VERSION 5.7 ;
  NOWIREEXTENSIONATPIN ON ;
  DIVIDERCHAR "/" ;
  BUSBITCHARS "[]" ;
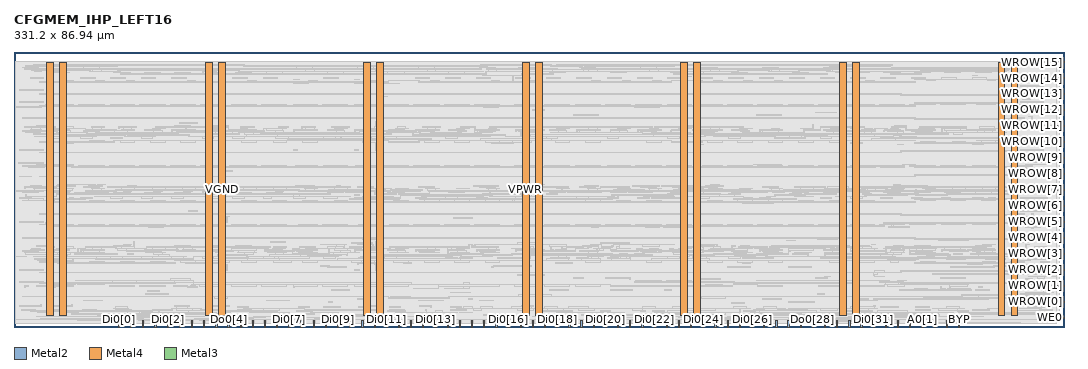
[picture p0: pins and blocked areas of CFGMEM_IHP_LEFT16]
MACRO CFGMEM_IHP_LEFT16
  CLASS BLOCK ;
  FOREIGN CFGMEM_IHP_LEFT16 ;
  ORIGIN 0.000 0.000 ;
  SIZE 331.200 BY 86.940 ;
  PIN A0[0]
    DIRECTION INPUT ;
    USE SIGNAL ;
    ANTENNAGATEAREA 0.213200 ;
    ANTENNADIFFAREA 2.015400 ;
    PORT
      LAYER Metal2 ;
        RECT 282.520 0.000 282.920 2.000 ;
    END
  END A0[0]
  PIN A0[1]
    DIRECTION INPUT ;
    USE SIGNAL ;
    ANTENNAGATEAREA 0.213200 ;
    ANTENNADIFFAREA 2.015400 ;
    PORT
      LAYER Metal2 ;
        RECT 286.360 0.000 286.760 2.000 ;
    END
  END A0[1]
  PIN A0[2]
    DIRECTION INPUT ;
    USE SIGNAL ;
    ANTENNAGATEAREA 0.213200 ;
    ANTENNADIFFAREA 2.015400 ;
    PORT
      LAYER Metal2 ;
        RECT 290.200 0.000 290.600 2.000 ;
    END
  END A0[2]
  PIN A0[3]
    DIRECTION INPUT ;
    USE SIGNAL ;
    ANTENNAGATEAREA 0.213200 ;
    ANTENNADIFFAREA 2.015400 ;
    PORT
      LAYER Metal2 ;
        RECT 294.040 0.000 294.440 2.000 ;
    END
  END A0[3]
  PIN BYP
    DIRECTION INPUT ;
    USE SIGNAL ;
    ANTENNAGATEAREA 0.213200 ;
    ANTENNADIFFAREA 2.015400 ;
    PORT
      LAYER Metal2 ;
        RECT 297.880 0.000 298.280 2.000 ;
    END
  END BYP
  PIN Di0[0]
    DIRECTION INPUT ;
    USE SIGNAL ;
    ANTENNAGATEAREA 0.406900 ;
    ANTENNADIFFAREA 4.030800 ;
    PORT
      LAYER Metal2 ;
        RECT 32.920 0.000 33.320 2.000 ;
    END
  END Di0[0]
  PIN Di0[10]
    DIRECTION INPUT ;
    USE SIGNAL ;
    ANTENNAGATEAREA 0.406900 ;
    ANTENNADIFFAREA 4.030800 ;
    PORT
      LAYER Metal2 ;
        RECT 109.720 0.000 110.120 2.000 ;
    END
  END Di0[10]
  PIN Di0[11]
    DIRECTION INPUT ;
    USE SIGNAL ;
    ANTENNAGATEAREA 0.406900 ;
    ANTENNADIFFAREA 4.030800 ;
    PORT
      LAYER Metal2 ;
        RECT 117.400 0.000 117.800 2.000 ;
    END
  END Di0[11]
  PIN Di0[12]
    DIRECTION INPUT ;
    USE SIGNAL ;
    ANTENNAGATEAREA 0.406900 ;
    ANTENNADIFFAREA 4.030800 ;
    PORT
      LAYER Metal2 ;
        RECT 125.080 0.000 125.480 2.000 ;
    END
  END Di0[12]
  PIN Di0[13]
    DIRECTION INPUT ;
    USE SIGNAL ;
    ANTENNAGATEAREA 0.406900 ;
    ANTENNADIFFAREA 4.030800 ;
    PORT
      LAYER Metal2 ;
        RECT 132.760 0.000 133.160 2.000 ;
    END
  END Di0[13]
  PIN Di0[14]
    DIRECTION INPUT ;
    USE SIGNAL ;
    ANTENNAGATEAREA 0.406900 ;
    ANTENNADIFFAREA 4.030800 ;
    PORT
      LAYER Metal2 ;
        RECT 140.440 0.000 140.840 2.000 ;
    END
  END Di0[14]
  PIN Di0[15]
    DIRECTION INPUT ;
    USE SIGNAL ;
    ANTENNAGATEAREA 0.406900 ;
    ANTENNADIFFAREA 4.030800 ;
    PORT
      LAYER Metal2 ;
        RECT 148.120 0.000 148.520 2.000 ;
    END
  END Di0[15]
  PIN Di0[16]
    DIRECTION INPUT ;
    USE SIGNAL ;
    ANTENNAGATEAREA 0.406900 ;
    ANTENNADIFFAREA 4.030800 ;
    PORT
      LAYER Metal2 ;
        RECT 155.800 0.000 156.200 2.000 ;
    END
  END Di0[16]
  PIN Di0[17]
    DIRECTION INPUT ;
    USE SIGNAL ;
    ANTENNAGATEAREA 0.406900 ;
    ANTENNADIFFAREA 4.030800 ;
    PORT
      LAYER Metal2 ;
        RECT 163.480 0.000 163.880 2.000 ;
    END
  END Di0[17]
  PIN Di0[18]
    DIRECTION INPUT ;
    USE SIGNAL ;
    ANTENNAGATEAREA 0.406900 ;
    ANTENNADIFFAREA 4.030800 ;
    PORT
      LAYER Metal2 ;
        RECT 171.160 0.000 171.560 2.000 ;
    END
  END Di0[18]
  PIN Di0[19]
    DIRECTION INPUT ;
    USE SIGNAL ;
    ANTENNAGATEAREA 0.406900 ;
    ANTENNADIFFAREA 4.030800 ;
    PORT
      LAYER Metal2 ;
        RECT 178.840 0.000 179.240 2.000 ;
    END
  END Di0[19]
  PIN Di0[1]
    DIRECTION INPUT ;
    USE SIGNAL ;
    ANTENNAGATEAREA 0.406900 ;
    ANTENNADIFFAREA 4.030800 ;
    PORT
      LAYER Metal2 ;
        RECT 40.600 0.000 41.000 2.000 ;
    END
  END Di0[1]
  PIN Di0[20]
    DIRECTION INPUT ;
    USE SIGNAL ;
    ANTENNAGATEAREA 0.406900 ;
    ANTENNADIFFAREA 4.030800 ;
    PORT
      LAYER Metal2 ;
        RECT 186.520 0.000 186.920 2.000 ;
    END
  END Di0[20]
  PIN Di0[21]
    DIRECTION INPUT ;
    USE SIGNAL ;
    ANTENNAGATEAREA 0.406900 ;
    ANTENNADIFFAREA 4.030800 ;
    PORT
      LAYER Metal2 ;
        RECT 194.200 0.000 194.600 2.000 ;
    END
  END Di0[21]
  PIN Di0[22]
    DIRECTION INPUT ;
    USE SIGNAL ;
    ANTENNAGATEAREA 0.406900 ;
    ANTENNADIFFAREA 4.030800 ;
    PORT
      LAYER Metal2 ;
        RECT 201.880 0.000 202.280 2.000 ;
    END
  END Di0[22]
  PIN Di0[23]
    DIRECTION INPUT ;
    USE SIGNAL ;
    ANTENNAGATEAREA 0.406900 ;
    ANTENNADIFFAREA 4.030800 ;
    PORT
      LAYER Metal2 ;
        RECT 209.560 0.000 209.960 2.000 ;
    END
  END Di0[23]
  PIN Di0[24]
    DIRECTION INPUT ;
    USE SIGNAL ;
    ANTENNAGATEAREA 0.406900 ;
    ANTENNADIFFAREA 4.030800 ;
    PORT
      LAYER Metal2 ;
        RECT 217.240 0.000 217.640 2.000 ;
    END
  END Di0[24]
  PIN Di0[25]
    DIRECTION INPUT ;
    USE SIGNAL ;
    ANTENNAGATEAREA 0.406900 ;
    ANTENNADIFFAREA 4.030800 ;
    PORT
      LAYER Metal2 ;
        RECT 224.920 0.000 225.320 2.000 ;
    END
  END Di0[25]
  PIN Di0[26]
    DIRECTION INPUT ;
    USE SIGNAL ;
    ANTENNAGATEAREA 0.406900 ;
    ANTENNADIFFAREA 4.030800 ;
    PORT
      LAYER Metal2 ;
        RECT 232.600 0.000 233.000 2.000 ;
    END
  END Di0[26]
  PIN Di0[27]
    DIRECTION INPUT ;
    USE SIGNAL ;
    ANTENNAGATEAREA 0.406900 ;
    ANTENNADIFFAREA 4.030800 ;
    PORT
      LAYER Metal2 ;
        RECT 240.280 0.000 240.680 2.000 ;
    END
  END Di0[27]
  PIN Di0[28]
    DIRECTION INPUT ;
    USE SIGNAL ;
    ANTENNAGATEAREA 0.406900 ;
    ANTENNADIFFAREA 4.030800 ;
    PORT
      LAYER Metal2 ;
        RECT 247.960 0.000 248.360 2.000 ;
    END
  END Di0[28]
  PIN Di0[29]
    DIRECTION INPUT ;
    USE SIGNAL ;
    ANTENNAGATEAREA 0.406900 ;
    ANTENNADIFFAREA 4.030800 ;
    PORT
      LAYER Metal2 ;
        RECT 255.640 0.000 256.040 2.000 ;
    END
  END Di0[29]
  PIN Di0[2]
    DIRECTION INPUT ;
    USE SIGNAL ;
    ANTENNAGATEAREA 0.406900 ;
    ANTENNADIFFAREA 4.030800 ;
    PORT
      LAYER Metal2 ;
        RECT 48.280 0.000 48.680 2.000 ;
    END
  END Di0[2]
  PIN Di0[30]
    DIRECTION INPUT ;
    USE SIGNAL ;
    ANTENNAGATEAREA 0.406900 ;
    ANTENNADIFFAREA 4.030800 ;
    PORT
      LAYER Metal2 ;
        RECT 263.320 0.000 263.720 2.000 ;
    END
  END Di0[30]
  PIN Di0[31]
    DIRECTION INPUT ;
    USE SIGNAL ;
    ANTENNAGATEAREA 0.406900 ;
    ANTENNADIFFAREA 4.030800 ;
    PORT
      LAYER Metal2 ;
        RECT 271.000 0.000 271.400 2.000 ;
    END
  END Di0[31]
  PIN Di0[3]
    DIRECTION INPUT ;
    USE SIGNAL ;
    ANTENNAGATEAREA 0.406900 ;
    ANTENNADIFFAREA 4.030800 ;
    PORT
      LAYER Metal2 ;
        RECT 55.960 0.000 56.360 2.000 ;
    END
  END Di0[3]
  PIN Di0[4]
    DIRECTION INPUT ;
    USE SIGNAL ;
    ANTENNAGATEAREA 0.406900 ;
    ANTENNADIFFAREA 4.030800 ;
    PORT
      LAYER Metal2 ;
        RECT 63.640 0.000 64.040 2.000 ;
    END
  END Di0[4]
  PIN Di0[5]
    DIRECTION INPUT ;
    USE SIGNAL ;
    ANTENNAGATEAREA 0.406900 ;
    ANTENNADIFFAREA 4.030800 ;
    PORT
      LAYER Metal2 ;
        RECT 71.320 0.000 71.720 2.000 ;
    END
  END Di0[5]
  PIN Di0[6]
    DIRECTION INPUT ;
    USE SIGNAL ;
    ANTENNAGATEAREA 0.406900 ;
    ANTENNADIFFAREA 4.030800 ;
    PORT
      LAYER Metal2 ;
        RECT 79.000 0.000 79.400 2.000 ;
    END
  END Di0[6]
  PIN Di0[7]
    DIRECTION INPUT ;
    USE SIGNAL ;
    ANTENNAGATEAREA 0.406900 ;
    ANTENNADIFFAREA 4.030800 ;
    PORT
      LAYER Metal2 ;
        RECT 86.680 0.000 87.080 2.000 ;
    END
  END Di0[7]
  PIN Di0[8]
    DIRECTION INPUT ;
    USE SIGNAL ;
    ANTENNAGATEAREA 0.406900 ;
    ANTENNADIFFAREA 4.030800 ;
    PORT
      LAYER Metal2 ;
        RECT 94.360 0.000 94.760 2.000 ;
    END
  END Di0[8]
  PIN Di0[9]
    DIRECTION INPUT ;
    USE SIGNAL ;
    ANTENNAGATEAREA 0.406900 ;
    ANTENNADIFFAREA 4.030800 ;
    PORT
      LAYER Metal2 ;
        RECT 102.040 0.000 102.440 2.000 ;
    END
  END Di0[9]
  PIN Do0[0]
    DIRECTION OUTPUT ;
    USE SIGNAL ;
    ANTENNADIFFAREA 1.023000 ;
    PORT
      LAYER Metal2 ;
        RECT 36.760 0.000 37.160 2.000 ;
    END
  END Do0[0]
  PIN Do0[10]
    DIRECTION OUTPUT ;
    USE SIGNAL ;
    ANTENNADIFFAREA 1.023000 ;
    PORT
      LAYER Metal2 ;
        RECT 113.560 0.000 113.960 2.000 ;
    END
  END Do0[10]
  PIN Do0[11]
    DIRECTION OUTPUT ;
    USE SIGNAL ;
    ANTENNADIFFAREA 1.023000 ;
    PORT
      LAYER Metal2 ;
        RECT 121.240 0.000 121.640 2.000 ;
    END
  END Do0[11]
  PIN Do0[12]
    DIRECTION OUTPUT ;
    USE SIGNAL ;
    ANTENNADIFFAREA 1.023000 ;
    PORT
      LAYER Metal2 ;
        RECT 128.920 0.000 129.320 2.000 ;
    END
  END Do0[12]
  PIN Do0[13]
    DIRECTION OUTPUT ;
    USE SIGNAL ;
    ANTENNADIFFAREA 1.023000 ;
    PORT
      LAYER Metal2 ;
        RECT 136.600 0.000 137.000 2.000 ;
    END
  END Do0[13]
  PIN Do0[14]
    DIRECTION OUTPUT ;
    USE SIGNAL ;
    ANTENNADIFFAREA 1.023000 ;
    PORT
      LAYER Metal2 ;
        RECT 144.280 0.000 144.680 2.000 ;
    END
  END Do0[14]
  PIN Do0[15]
    DIRECTION OUTPUT ;
    USE SIGNAL ;
    ANTENNADIFFAREA 1.023000 ;
    PORT
      LAYER Metal2 ;
        RECT 151.960 0.000 152.360 2.000 ;
    END
  END Do0[15]
  PIN Do0[16]
    DIRECTION OUTPUT ;
    USE SIGNAL ;
    ANTENNADIFFAREA 1.023000 ;
    PORT
      LAYER Metal2 ;
        RECT 159.640 0.000 160.040 2.000 ;
    END
  END Do0[16]
  PIN Do0[17]
    DIRECTION OUTPUT ;
    USE SIGNAL ;
    ANTENNADIFFAREA 1.023000 ;
    PORT
      LAYER Metal2 ;
        RECT 167.320 0.000 167.720 2.000 ;
    END
  END Do0[17]
  PIN Do0[18]
    DIRECTION OUTPUT ;
    USE SIGNAL ;
    ANTENNADIFFAREA 1.023000 ;
    PORT
      LAYER Metal2 ;
        RECT 175.000 0.000 175.400 2.000 ;
    END
  END Do0[18]
  PIN Do0[19]
    DIRECTION OUTPUT ;
    USE SIGNAL ;
    ANTENNADIFFAREA 1.023000 ;
    PORT
      LAYER Metal2 ;
        RECT 182.680 0.000 183.080 2.000 ;
    END
  END Do0[19]
  PIN Do0[1]
    DIRECTION OUTPUT ;
    USE SIGNAL ;
    ANTENNADIFFAREA 1.023000 ;
    PORT
      LAYER Metal2 ;
        RECT 44.440 0.000 44.840 2.000 ;
    END
  END Do0[1]
  PIN Do0[20]
    DIRECTION OUTPUT ;
    USE SIGNAL ;
    ANTENNADIFFAREA 1.023000 ;
    PORT
      LAYER Metal2 ;
        RECT 190.360 0.000 190.760 2.000 ;
    END
  END Do0[20]
  PIN Do0[21]
    DIRECTION OUTPUT ;
    USE SIGNAL ;
    ANTENNADIFFAREA 1.023000 ;
    PORT
      LAYER Metal2 ;
        RECT 198.040 0.000 198.440 2.000 ;
    END
  END Do0[21]
  PIN Do0[22]
    DIRECTION OUTPUT ;
    USE SIGNAL ;
    ANTENNADIFFAREA 1.023000 ;
    PORT
      LAYER Metal2 ;
        RECT 205.720 0.000 206.120 2.000 ;
    END
  END Do0[22]
  PIN Do0[23]
    DIRECTION OUTPUT ;
    USE SIGNAL ;
    ANTENNADIFFAREA 1.023000 ;
    PORT
      LAYER Metal2 ;
        RECT 213.400 0.000 213.800 2.000 ;
    END
  END Do0[23]
  PIN Do0[24]
    DIRECTION OUTPUT ;
    USE SIGNAL ;
    ANTENNADIFFAREA 1.023000 ;
    PORT
      LAYER Metal2 ;
        RECT 221.080 0.000 221.480 2.000 ;
    END
  END Do0[24]
  PIN Do0[25]
    DIRECTION OUTPUT ;
    USE SIGNAL ;
    ANTENNADIFFAREA 1.023000 ;
    PORT
      LAYER Metal2 ;
        RECT 228.760 0.000 229.160 2.000 ;
    END
  END Do0[25]
  PIN Do0[26]
    DIRECTION OUTPUT ;
    USE SIGNAL ;
    ANTENNADIFFAREA 1.023000 ;
    PORT
      LAYER Metal2 ;
        RECT 236.440 0.000 236.840 2.000 ;
    END
  END Do0[26]
  PIN Do0[27]
    DIRECTION OUTPUT ;
    USE SIGNAL ;
    ANTENNADIFFAREA 1.023000 ;
    PORT
      LAYER Metal2 ;
        RECT 244.120 0.000 244.520 2.000 ;
    END
  END Do0[27]
  PIN Do0[28]
    DIRECTION OUTPUT ;
    USE SIGNAL ;
    ANTENNADIFFAREA 1.023000 ;
    PORT
      LAYER Metal2 ;
        RECT 251.800 0.000 252.200 2.000 ;
    END
  END Do0[28]
  PIN Do0[29]
    DIRECTION OUTPUT ;
    USE SIGNAL ;
    ANTENNADIFFAREA 1.023000 ;
    PORT
      LAYER Metal2 ;
        RECT 259.480 0.000 259.880 2.000 ;
    END
  END Do0[29]
  PIN Do0[2]
    DIRECTION OUTPUT ;
    USE SIGNAL ;
    ANTENNADIFFAREA 1.023000 ;
    PORT
      LAYER Metal2 ;
        RECT 52.120 0.000 52.520 2.000 ;
    END
  END Do0[2]
  PIN Do0[30]
    DIRECTION OUTPUT ;
    USE SIGNAL ;
    ANTENNADIFFAREA 1.023000 ;
    PORT
      LAYER Metal2 ;
        RECT 267.160 0.000 267.560 2.000 ;
    END
  END Do0[30]
  PIN Do0[31]
    DIRECTION OUTPUT ;
    USE SIGNAL ;
    ANTENNADIFFAREA 1.023000 ;
    PORT
      LAYER Metal2 ;
        RECT 274.840 0.000 275.240 2.000 ;
    END
  END Do0[31]
  PIN Do0[3]
    DIRECTION OUTPUT ;
    USE SIGNAL ;
    ANTENNADIFFAREA 1.023000 ;
    PORT
      LAYER Metal2 ;
        RECT 59.800 0.000 60.200 2.000 ;
    END
  END Do0[3]
  PIN Do0[4]
    DIRECTION OUTPUT ;
    USE SIGNAL ;
    ANTENNADIFFAREA 1.023000 ;
    PORT
      LAYER Metal2 ;
        RECT 67.480 0.000 67.880 2.000 ;
    END
  END Do0[4]
  PIN Do0[5]
    DIRECTION OUTPUT ;
    USE SIGNAL ;
    ANTENNADIFFAREA 1.023000 ;
    PORT
      LAYER Metal2 ;
        RECT 75.160 0.000 75.560 2.000 ;
    END
  END Do0[5]
  PIN Do0[6]
    DIRECTION OUTPUT ;
    USE SIGNAL ;
    ANTENNADIFFAREA 1.023000 ;
    PORT
      LAYER Metal2 ;
        RECT 82.840 0.000 83.240 2.000 ;
    END
  END Do0[6]
  PIN Do0[7]
    DIRECTION OUTPUT ;
    USE SIGNAL ;
    ANTENNADIFFAREA 1.023000 ;
    PORT
      LAYER Metal2 ;
        RECT 90.520 0.000 90.920 2.000 ;
    END
  END Do0[7]
  PIN Do0[8]
    DIRECTION OUTPUT ;
    USE SIGNAL ;
    ANTENNADIFFAREA 1.023000 ;
    PORT
      LAYER Metal2 ;
        RECT 98.200 0.000 98.600 2.000 ;
    END
  END Do0[8]
  PIN Do0[9]
    DIRECTION OUTPUT ;
    USE SIGNAL ;
    ANTENNADIFFAREA 1.023000 ;
    PORT
      LAYER Metal2 ;
        RECT 105.880 0.000 106.280 2.000 ;
    END
  END Do0[9]
  PIN EN0
    DIRECTION INPUT ;
    USE SIGNAL ;
    ANTENNAGATEAREA 0.373100 ;
    ANTENNADIFFAREA 4.030800 ;
    PORT
      LAYER Metal2 ;
        RECT 278.680 0.000 279.080 2.000 ;
    END
  END EN0
  PIN VGND
    DIRECTION INOUT ;
    USE GROUND ;
    PORT
      LAYER Metal4 ;
        RECT 14.490 3.560 16.590 83.380 ;
    END
    PORT
      LAYER Metal4 ;
        RECT 64.490 3.560 66.590 83.380 ;
    END
    PORT
      LAYER Metal4 ;
        RECT 114.490 3.560 116.590 83.380 ;
    END
    PORT
      LAYER Metal4 ;
        RECT 164.490 3.560 166.590 83.380 ;
    END
    PORT
      LAYER Metal4 ;
        RECT 214.490 3.560 216.590 83.380 ;
    END
    PORT
      LAYER Metal4 ;
        RECT 264.490 3.560 266.590 83.380 ;
    END
    PORT
      LAYER Metal4 ;
        RECT 314.490 3.560 316.590 83.380 ;
    END
  END VGND
  PIN VPWR
    DIRECTION INOUT ;
    USE POWER ;
    PORT
      LAYER Metal4 ;
        RECT 10.390 3.560 12.490 83.380 ;
    END
    PORT
      LAYER Metal4 ;
        RECT 60.390 3.560 62.490 83.380 ;
    END
    PORT
      LAYER Metal4 ;
        RECT 110.390 3.560 112.490 83.380 ;
    END
    PORT
      LAYER Metal4 ;
        RECT 160.390 3.560 162.490 83.380 ;
    END
    PORT
      LAYER Metal4 ;
        RECT 210.390 3.560 212.490 83.380 ;
    END
    PORT
      LAYER Metal4 ;
        RECT 260.390 3.560 262.490 83.380 ;
    END
    PORT
      LAYER Metal4 ;
        RECT 310.390 3.560 312.490 83.380 ;
    END
  END VPWR
  PIN WE0
    DIRECTION INPUT ;
    USE SIGNAL ;
    ANTENNAGATEAREA 3.078400 ;
    ANTENNADIFFAREA 32.246399 ;
    PORT
      LAYER Metal3 ;
        RECT 329.200 2.740 331.200 3.140 ;
    END
  END WE0
  PIN WROW[0]
    DIRECTION INPUT ;
    USE SIGNAL ;
    ANTENNAGATEAREA 0.192400 ;
    ANTENNADIFFAREA 2.015400 ;
    PORT
      LAYER Metal3 ;
        RECT 329.200 7.780 331.200 8.180 ;
    END
  END WROW[0]
  PIN WROW[10]
    DIRECTION INPUT ;
    USE SIGNAL ;
    ANTENNAGATEAREA 0.192400 ;
    ANTENNADIFFAREA 2.015400 ;
    PORT
      LAYER Metal3 ;
        RECT 329.200 58.180 331.200 58.580 ;
    END
  END WROW[10]
  PIN WROW[11]
    DIRECTION INPUT ;
    USE SIGNAL ;
    ANTENNAGATEAREA 0.192400 ;
    ANTENNADIFFAREA 2.015400 ;
    PORT
      LAYER Metal3 ;
        RECT 329.200 63.220 331.200 63.620 ;
    END
  END WROW[11]
  PIN WROW[12]
    DIRECTION INPUT ;
    USE SIGNAL ;
    ANTENNAGATEAREA 0.192400 ;
    ANTENNADIFFAREA 2.015400 ;
    PORT
      LAYER Metal3 ;
        RECT 329.200 68.260 331.200 68.660 ;
    END
  END WROW[12]
  PIN WROW[13]
    DIRECTION INPUT ;
    USE SIGNAL ;
    ANTENNAGATEAREA 0.192400 ;
    ANTENNADIFFAREA 2.015400 ;
    PORT
      LAYER Metal3 ;
        RECT 329.200 73.300 331.200 73.700 ;
    END
  END WROW[13]
  PIN WROW[14]
    DIRECTION INPUT ;
    USE SIGNAL ;
    ANTENNAGATEAREA 0.192400 ;
    ANTENNADIFFAREA 2.015400 ;
    PORT
      LAYER Metal3 ;
        RECT 329.200 78.340 331.200 78.740 ;
    END
  END WROW[14]
  PIN WROW[15]
    DIRECTION INPUT ;
    USE SIGNAL ;
    ANTENNAGATEAREA 0.192400 ;
    ANTENNADIFFAREA 2.015400 ;
    PORT
      LAYER Metal3 ;
        RECT 329.200 83.380 331.200 83.780 ;
    END
  END WROW[15]
  PIN WROW[1]
    DIRECTION INPUT ;
    USE SIGNAL ;
    ANTENNAGATEAREA 0.192400 ;
    ANTENNADIFFAREA 2.015400 ;
    PORT
      LAYER Metal3 ;
        RECT 329.200 12.820 331.200 13.220 ;
    END
  END WROW[1]
  PIN WROW[2]
    DIRECTION INPUT ;
    USE SIGNAL ;
    ANTENNAGATEAREA 0.192400 ;
    ANTENNADIFFAREA 2.015400 ;
    PORT
      LAYER Metal3 ;
        RECT 329.200 17.860 331.200 18.260 ;
    END
  END WROW[2]
  PIN WROW[3]
    DIRECTION INPUT ;
    USE SIGNAL ;
    ANTENNAGATEAREA 0.192400 ;
    ANTENNADIFFAREA 2.015400 ;
    PORT
      LAYER Metal3 ;
        RECT 329.200 22.900 331.200 23.300 ;
    END
  END WROW[3]
  PIN WROW[4]
    DIRECTION INPUT ;
    USE SIGNAL ;
    ANTENNAGATEAREA 0.192400 ;
    ANTENNADIFFAREA 2.015400 ;
    PORT
      LAYER Metal3 ;
        RECT 329.200 27.940 331.200 28.340 ;
    END
  END WROW[4]
  PIN WROW[5]
    DIRECTION INPUT ;
    USE SIGNAL ;
    ANTENNAGATEAREA 0.192400 ;
    ANTENNADIFFAREA 2.015400 ;
    PORT
      LAYER Metal3 ;
        RECT 329.200 32.980 331.200 33.380 ;
    END
  END WROW[5]
  PIN WROW[6]
    DIRECTION INPUT ;
    USE SIGNAL ;
    ANTENNAGATEAREA 0.192400 ;
    ANTENNADIFFAREA 2.015400 ;
    PORT
      LAYER Metal3 ;
        RECT 329.200 38.020 331.200 38.420 ;
    END
  END WROW[6]
  PIN WROW[7]
    DIRECTION INPUT ;
    USE SIGNAL ;
    ANTENNAGATEAREA 0.192400 ;
    ANTENNADIFFAREA 2.015400 ;
    PORT
      LAYER Metal3 ;
        RECT 329.200 43.060 331.200 43.460 ;
    END
  END WROW[7]
  PIN WROW[8]
    DIRECTION INPUT ;
    USE SIGNAL ;
    ANTENNAGATEAREA 0.192400 ;
    ANTENNADIFFAREA 2.015400 ;
    PORT
      LAYER Metal3 ;
        RECT 329.200 48.100 331.200 48.500 ;
    END
  END WROW[8]
  PIN WROW[9]
    DIRECTION INPUT ;
    USE SIGNAL ;
    ANTENNAGATEAREA 0.192400 ;
    ANTENNADIFFAREA 2.015400 ;
    PORT
      LAYER Metal3 ;
        RECT 329.200 53.140 331.200 53.540 ;
    END
  END WROW[9]
  OBS
      LAYER GatPoly ;
        RECT 1.440 3.630 329.760 83.310 ;
      LAYER Metal1 ;
        RECT 1.440 3.560 329.760 83.380 ;
      LAYER Metal2 ;
        RECT 0.375 2.210 328.905 83.725 ;
        RECT 0.375 1.115 32.710 2.210 ;
        RECT 33.530 1.115 36.550 2.210 ;
        RECT 37.370 1.115 40.390 2.210 ;
        RECT 41.210 1.115 44.230 2.210 ;
        RECT 45.050 1.115 48.070 2.210 ;
        RECT 48.890 1.115 51.910 2.210 ;
        RECT 52.730 1.115 55.750 2.210 ;
        RECT 56.570 1.115 59.590 2.210 ;
        RECT 60.410 1.115 63.430 2.210 ;
        RECT 64.250 1.115 67.270 2.210 ;
        RECT 68.090 1.115 71.110 2.210 ;
        RECT 71.930 1.115 74.950 2.210 ;
        RECT 75.770 1.115 78.790 2.210 ;
        RECT 79.610 1.115 82.630 2.210 ;
        RECT 83.450 1.115 86.470 2.210 ;
        RECT 87.290 1.115 90.310 2.210 ;
        RECT 91.130 1.115 94.150 2.210 ;
        RECT 94.970 1.115 97.990 2.210 ;
        RECT 98.810 1.115 101.830 2.210 ;
        RECT 102.650 1.115 105.670 2.210 ;
        RECT 106.490 1.115 109.510 2.210 ;
        RECT 110.330 1.115 113.350 2.210 ;
        RECT 114.170 1.115 117.190 2.210 ;
        RECT 118.010 1.115 121.030 2.210 ;
        RECT 121.850 1.115 124.870 2.210 ;
        RECT 125.690 1.115 128.710 2.210 ;
        RECT 129.530 1.115 132.550 2.210 ;
        RECT 133.370 1.115 136.390 2.210 ;
        RECT 137.210 1.115 140.230 2.210 ;
        RECT 141.050 1.115 144.070 2.210 ;
        RECT 144.890 1.115 147.910 2.210 ;
        RECT 148.730 1.115 151.750 2.210 ;
        RECT 152.570 1.115 155.590 2.210 ;
        RECT 156.410 1.115 159.430 2.210 ;
        RECT 160.250 1.115 163.270 2.210 ;
        RECT 164.090 1.115 167.110 2.210 ;
        RECT 167.930 1.115 170.950 2.210 ;
        RECT 171.770 1.115 174.790 2.210 ;
        RECT 175.610 1.115 178.630 2.210 ;
        RECT 179.450 1.115 182.470 2.210 ;
        RECT 183.290 1.115 186.310 2.210 ;
        RECT 187.130 1.115 190.150 2.210 ;
        RECT 190.970 1.115 193.990 2.210 ;
        RECT 194.810 1.115 197.830 2.210 ;
        RECT 198.650 1.115 201.670 2.210 ;
        RECT 202.490 1.115 205.510 2.210 ;
        RECT 206.330 1.115 209.350 2.210 ;
        RECT 210.170 1.115 213.190 2.210 ;
        RECT 214.010 1.115 217.030 2.210 ;
        RECT 217.850 1.115 220.870 2.210 ;
        RECT 221.690 1.115 224.710 2.210 ;
        RECT 225.530 1.115 228.550 2.210 ;
        RECT 229.370 1.115 232.390 2.210 ;
        RECT 233.210 1.115 236.230 2.210 ;
        RECT 237.050 1.115 240.070 2.210 ;
        RECT 240.890 1.115 243.910 2.210 ;
        RECT 244.730 1.115 247.750 2.210 ;
        RECT 248.570 1.115 251.590 2.210 ;
        RECT 252.410 1.115 255.430 2.210 ;
        RECT 256.250 1.115 259.270 2.210 ;
        RECT 260.090 1.115 263.110 2.210 ;
        RECT 263.930 1.115 266.950 2.210 ;
        RECT 267.770 1.115 270.790 2.210 ;
        RECT 271.610 1.115 274.630 2.210 ;
        RECT 275.450 1.115 278.470 2.210 ;
        RECT 279.290 1.115 282.310 2.210 ;
        RECT 283.130 1.115 286.150 2.210 ;
        RECT 286.970 1.115 289.990 2.210 ;
        RECT 290.810 1.115 293.830 2.210 ;
        RECT 294.650 1.115 297.670 2.210 ;
        RECT 298.490 1.115 328.905 2.210 ;
     LAYER Metal3 ;
        RECT 163.535 3.260 167.185 3.460 ;
        RECT 164.575 3.460 166.505 3.880 ;
        RECT 248.060 1.580 272.785 1.780 ;
        RECT 248.060 1.780 248.305 2.000 ;
        RECT 251.855 1.780 272.785 2.000 ;
        RECT 217.295 2.000 234.385 2.200 ;
        RECT 251.855 2.000 277.105 2.200 ;
        RECT 221.135 2.200 234.385 2.420 ;
        RECT 248.015 2.000 248.305 2.420 ;
        RECT 251.855 2.200 267.025 2.420 ;
        RECT 221.135 2.420 238.705 2.620 ;
        RECT 244.175 2.420 267.025 2.620 ;
        RECT 221.135 2.620 230.545 2.840 ;
        RECT 236.495 2.620 238.705 2.840 ;
        RECT 244.175 2.620 257.905 2.840 ;
        RECT 259.535 2.620 267.025 2.840 ;
        RECT 236.495 2.840 257.905 3.040 ;
        RECT 259.535 2.840 286.225 3.040 ;
        RECT 209.615 2.840 230.545 3.040 ;
        RECT 209.615 3.040 219.505 3.260 ;
        RECT 224.975 3.040 230.545 3.260 ;
        RECT 232.655 2.620 235.780 3.260 ;
        RECT 274.895 3.040 286.225 3.260 ;
        RECT 205.775 3.260 219.505 3.460 ;
        RECT 224.975 3.260 235.780 3.460 ;
        RECT 263.375 3.040 266.980 3.460 ;
        RECT 274.895 3.260 305.905 3.460 ;
        RECT 205.775 3.460 207.985 3.680 ;
        RECT 235.580 3.460 235.780 3.680 ;
        RECT 264.575 3.460 266.980 3.680 ;
        RECT 274.895 3.460 291.985 3.680 ;
        RECT 228.815 3.460 229.105 3.880 ;
        RECT 264.575 3.680 291.985 3.880 ;
        RECT 235.580 3.680 262.705 3.880 ;
        RECT 204.335 3.680 207.985 4.100 ;
        RECT 214.575 3.460 216.505 4.100 ;
        RECT 228.860 3.880 229.105 4.100 ;
        RECT 235.580 3.880 248.305 4.100 ;
        RECT 255.695 3.880 262.705 4.100 ;
        RECT 264.575 3.880 291.505 4.100 ;
        RECT 198.095 4.100 209.905 4.300 ;
        RECT 228.860 4.100 248.305 4.300 ;
        RECT 255.695 4.100 291.505 4.300 ;
        RECT 201.935 4.300 209.905 4.520 ;
        RECT 213.020 4.100 224.305 4.520 ;
        RECT 228.860 4.300 229.060 4.520 ;
        RECT 232.175 4.300 248.305 4.520 ;
        RECT 255.695 4.300 261.265 4.520 ;
        RECT 267.215 4.300 291.505 4.520 ;
        RECT 187.055 4.520 192.625 4.720 ;
        RECT 267.215 4.520 296.305 4.720 ;
        RECT 171.215 4.520 185.905 4.720 ;
        RECT 201.935 4.520 229.060 4.720 ;
        RECT 232.175 4.520 261.265 4.720 ;
        RECT 171.215 4.720 176.305 4.940 ;
        RECT 185.135 4.720 185.905 4.940 ;
        RECT 187.055 4.720 188.305 4.940 ;
        RECT 201.935 4.720 205.105 4.940 ;
        RECT 232.175 4.720 233.905 4.940 ;
        RECT 261.020 4.720 261.265 4.940 ;
        RECT 267.215 4.720 270.865 4.940 ;
        RECT 166.895 4.940 176.305 5.140 ;
        RECT 185.135 4.940 188.305 5.140 ;
        RECT 197.615 4.940 199.345 5.140 ;
        RECT 201.455 4.940 205.105 5.140 ;
        RECT 206.255 4.720 214.705 5.140 ;
        RECT 230.255 4.940 233.905 5.140 ;
        RECT 235.055 4.720 253.105 5.140 ;
        RECT 261.020 4.940 270.865 5.140 ;
        RECT 272.495 4.720 281.905 5.140 ;
        RECT 197.615 5.140 198.385 5.360 ;
        RECT 228.860 4.720 229.060 5.360 ;
        RECT 233.135 5.140 233.905 5.360 ;
        RECT 235.055 5.140 236.785 5.360 ;
        RECT 137.615 5.360 142.705 5.560 ;
        RECT 233.135 5.360 236.785 5.560 ;
        RECT 240.815 5.140 250.225 5.560 ;
        RECT 139.535 5.560 142.705 5.780 ;
        RECT 144.815 5.360 147.505 5.780 ;
        RECT 158.735 5.360 163.825 5.780 ;
        RECT 168.335 5.140 173.425 5.780 ;
        RECT 177.935 5.360 183.025 5.780 ;
        RECT 195.215 5.360 198.385 5.780 ;
        RECT 216.335 5.360 221.425 5.780 ;
        RECT 228.815 5.360 229.105 5.780 ;
        RECT 234.095 5.560 236.785 5.780 ;
        RECT 240.815 5.560 243.505 5.780 ;
        RECT 244.220 5.560 250.225 5.780 ;
        RECT 254.255 5.360 259.825 5.780 ;
        RECT 264.335 5.140 269.425 5.780 ;
        RECT 139.535 5.780 232.465 5.980 ;
        RECT 234.095 5.780 243.505 5.980 ;
        RECT 244.220 5.780 272.305 5.980 ;
        RECT 139.535 5.980 141.265 6.200 ;
        RECT 137.615 6.200 141.265 6.400 ;
        RECT 141.935 5.980 144.625 6.400 ;
        RECT 147.215 5.980 150.865 6.400 ;
        RECT 156.815 5.980 163.345 6.400 ;
        RECT 167.375 5.980 171.505 6.400 ;
        RECT 175.055 5.980 181.105 6.400 ;
        RECT 198.095 5.980 202.225 6.400 ;
        RECT 207.695 5.980 211.825 6.400 ;
        RECT 226.895 5.980 231.025 6.400 ;
        RECT 236.495 5.980 240.625 6.400 ;
        RECT 263.855 5.980 271.300 6.400 ;
        RECT 160.175 6.400 163.345 6.620 ;
        RECT 271.100 6.400 271.300 6.620 ;
        RECT 160.175 6.620 163.825 6.820 ;
        RECT 271.100 6.620 271.825 6.820 ;
        RECT 164.575 11.240 166.505 11.440 ;
        RECT 265.775 8.300 272.305 8.500 ;
        RECT 265.775 8.500 269.425 8.720 ;
        RECT 271.055 8.500 272.305 8.720 ;
        RECT 264.815 8.720 269.425 8.920 ;
        RECT 271.055 8.720 307.345 8.920 ;
        RECT 286.895 8.920 307.345 9.140 ;
        RECT 117.980 9.140 137.425 9.340 ;
        RECT 286.895 9.140 326.545 9.340 ;
        RECT 63.215 9.140 67.345 9.560 ;
        RECT 117.980 9.340 118.225 9.560 ;
        RECT 137.180 9.340 137.425 9.560 ;
        RECT 216.815 9.140 224.305 9.560 ;
        RECT 286.895 9.340 299.140 9.560 ;
        RECT 320.975 9.340 326.545 9.560 ;
        RECT 2.735 9.560 118.225 9.760 ;
        RECT 118.895 9.340 124.945 9.760 ;
        RECT 137.180 9.560 299.140 9.760 ;
        RECT 320.975 9.560 328.465 9.760 ;
        RECT 314.255 9.340 319.300 9.760 ;
        RECT 298.895 9.760 299.140 9.980 ;
        RECT 304.175 9.340 312.145 9.980 ;
        RECT 314.255 9.760 316.465 9.980 ;
        RECT 319.100 9.760 319.300 9.980 ;
        RECT 320.975 9.760 325.585 9.980 ;
        RECT 159.215 9.760 169.585 10.180 ;
        RECT 298.895 9.980 316.465 10.180 ;
        RECT 319.100 9.980 325.585 10.400 ;
        RECT 317.615 10.400 326.545 10.600 ;
        RECT 319.055 10.600 326.545 10.820 ;
        RECT 319.055 10.820 327.985 11.020 ;
        RECT 324.815 11.020 326.545 11.440 ;
        RECT 126.095 12.080 134.020 12.280 ;
        RECT 135.695 12.080 143.620 12.280 ;
        RECT 54.620 12.500 57.745 12.700 ;
        RECT 88.175 12.500 88.465 12.700 ;
        RECT 12.380 12.500 13.060 12.920 ;
        RECT 54.620 12.700 54.820 12.920 ;
        RECT 88.220 12.700 88.465 12.920 ;
        RECT 133.820 12.280 134.020 12.920 ;
        RECT 141.935 12.280 143.620 12.920 ;
        RECT 7.055 12.920 18.865 13.120 ;
        RECT 50.255 12.920 54.820 13.120 ;
        RECT 55.535 12.700 57.265 13.120 ;
        RECT 188.015 12.920 226.705 13.120 ;
        RECT 10.415 13.120 18.865 13.340 ;
        RECT 56.015 13.120 57.265 13.340 ;
        RECT 58.415 12.920 66.865 13.340 ;
        RECT 68.495 12.920 76.465 13.340 ;
        RECT 78.095 12.920 86.065 13.340 ;
        RECT 88.220 12.920 95.665 13.340 ;
        RECT 97.295 12.920 105.265 13.340 ;
        RECT 107.375 12.920 114.865 13.340 ;
        RECT 116.015 12.920 124.465 13.340 ;
        RECT 133.775 12.920 153.265 13.340 ;
        RECT 157.775 12.920 165.745 13.340 ;
        RECT 167.375 12.920 175.345 13.340 ;
        RECT 176.975 12.920 184.945 13.340 ;
        RECT 188.015 13.120 188.260 13.340 ;
        RECT 56.015 13.340 188.260 13.540 ;
        RECT 218.255 13.120 223.345 13.540 ;
        RECT 10.415 13.340 19.345 13.760 ;
        RECT 20.015 13.340 28.465 13.760 ;
        RECT 56.540 13.540 125.425 13.960 ;
        RECT 141.935 13.540 143.665 13.960 ;
        RECT 8.015 13.760 51.025 13.960 ;
        RECT 8.015 13.960 9.265 14.180 ;
        RECT 50.780 13.960 51.025 14.180 ;
        RECT 56.540 13.960 56.740 14.180 ;
        RECT 1.775 14.180 9.265 14.380 ;
        RECT 31.055 13.960 38.545 14.600 ;
        RECT 50.780 14.180 56.740 14.600 ;
        RECT 19.535 14.600 56.740 14.800 ;
        RECT 49.295 14.800 55.825 15.220 ;
        RECT 158.735 16.280 167.185 16.480 ;
        RECT 271.055 16.280 271.345 16.480 ;
        RECT 271.100 16.480 271.345 16.700 ;
        RECT 289.775 16.700 325.585 16.900 ;
        RECT 271.100 16.700 272.305 17.120 ;
        RECT 8.015 17.120 279.940 17.320 ;
        RECT 314.255 16.900 318.865 17.320 ;
        RECT 279.695 17.320 279.940 17.540 ;
        RECT 314.255 17.320 316.465 17.540 ;
        RECT 271.535 17.320 274.705 17.740 ;
        RECT 279.695 17.540 316.465 17.740 ;
        RECT 164.575 18.800 166.505 19.000 ;
        RECT 114.140 17.960 114.865 18.160 ;
        RECT 114.140 18.160 114.340 18.800 ;
        RECT 114.140 18.800 116.505 19.000 ;
        RECT 114.140 19.000 114.340 19.640 ;
        RECT 108.335 19.640 108.625 19.840 ;
        RECT 108.380 19.840 108.625 20.060 ;
        RECT 113.615 19.640 114.340 20.060 ;
        RECT 13.820 20.060 51.025 20.260 ;
        RECT 108.380 20.060 115.345 20.260 ;
        RECT 122.735 20.060 125.425 20.260 ;
        RECT 54.095 20.060 64.465 20.260 ;
        RECT 13.820 20.260 18.865 20.480 ;
        RECT 54.095 20.260 57.265 20.480 ;
        RECT 62.735 20.260 64.465 20.480 ;
        RECT 108.380 20.260 109.585 20.480 ;
        RECT 122.735 20.260 124.465 20.480 ;
        RECT 229.775 20.060 232.465 20.480 ;
        RECT 8.015 20.480 18.865 20.680 ;
        RECT 23.855 20.260 28.465 20.680 ;
        RECT 33.455 20.260 38.065 20.680 ;
        RECT 43.055 20.260 47.665 20.680 ;
        RECT 8.015 20.680 18.820 20.900 ;
        RECT 52.655 20.480 57.265 20.900 ;
        RECT 62.735 20.480 67.825 20.900 ;
        RECT 71.855 20.480 76.465 20.900 ;
        RECT 81.935 20.480 87.505 20.900 ;
        RECT 91.055 20.480 95.665 20.900 ;
        RECT 106.415 20.480 109.585 20.900 ;
        RECT 113.615 20.260 114.865 20.900 ;
        RECT 119.855 20.480 124.465 20.900 ;
        RECT 129.455 20.480 134.065 20.900 ;
        RECT 139.055 20.480 143.665 20.900 ;
        RECT 148.655 20.480 153.265 20.900 ;
        RECT 180.335 20.480 184.945 20.900 ;
        RECT 199.535 20.480 204.145 20.900 ;
        RECT 218.735 20.480 223.345 20.900 ;
        RECT 228.335 20.480 232.945 20.900 ;
        RECT 237.935 20.480 242.545 20.900 ;
        RECT 257.135 20.480 261.745 20.900 ;
        RECT 266.735 20.480 271.345 20.900 ;
        RECT 276.335 20.480 279.025 20.900 ;
        RECT 7.535 20.900 18.820 21.100 ;
        RECT 50.735 20.900 284.305 21.100 ;
        RECT 7.535 21.100 16.465 21.320 ;
        RECT 18.575 21.100 18.820 21.320 ;
        RECT 50.735 21.100 56.740 21.320 ;
        RECT 275.375 21.100 284.305 21.320 ;
        RECT 6.575 21.320 16.465 21.520 ;
        RECT 102.095 21.100 140.740 21.520 ;
        RECT 167.855 21.100 174.865 21.520 ;
        RECT 178.895 21.100 184.945 21.520 ;
        RECT 200.975 21.100 214.180 21.520 ;
        RECT 215.855 21.100 219.505 21.520 ;
        RECT 306.575 21.320 312.625 21.520 ;
        RECT 25.820 21.320 56.740 21.520 ;
        RECT 60.815 21.100 66.865 21.520 ;
        RECT 73.775 21.100 83.620 21.520 ;
        RECT 188.495 21.100 194.500 21.520 ;
        RECT 16.220 21.520 16.465 21.740 ;
        RECT 18.575 21.320 18.865 21.740 ;
        RECT 25.820 21.520 26.065 21.740 ;
        RECT 60.815 21.520 63.025 21.740 ;
        RECT 64.655 21.520 66.865 21.740 ;
        RECT 73.775 21.520 74.020 21.740 ;
        RECT 83.375 21.520 83.620 21.740 ;
        RECT 140.495 21.520 140.740 21.740 ;
        RECT 169.295 21.520 174.865 21.740 ;
        RECT 178.895 21.520 181.105 21.740 ;
        RECT 188.495 21.520 190.705 21.740 ;
        RECT 194.255 21.520 194.500 21.740 ;
        RECT 215.855 21.520 218.545 21.740 ;
        RECT 275.375 21.320 285.265 21.740 ;
        RECT 294.095 21.320 300.145 21.740 ;
        RECT 306.575 21.520 312.145 21.740 ;
        RECT 108.815 21.520 116.305 21.940 ;
        RECT 136.175 21.520 139.825 21.940 ;
        RECT 140.495 21.740 144.625 21.940 ;
        RECT 152.495 21.740 162.865 21.940 ;
        RECT 169.295 21.740 175.345 21.940 ;
        RECT 177.455 21.740 181.105 21.940 ;
        RECT 187.055 21.740 190.705 21.940 ;
        RECT 64.655 21.740 74.020 21.940 ;
        RECT 229.775 21.740 239.665 21.940 ;
        RECT 254.255 21.740 312.145 21.940 ;
        RECT 11.375 21.520 15.025 22.160 ;
        RECT 16.220 21.740 26.065 22.160 ;
        RECT 30.575 21.520 34.225 22.160 ;
        RECT 40.175 21.520 43.825 22.160 ;
        RECT 49.775 21.520 53.425 22.160 ;
        RECT 56.540 21.520 56.740 22.160 ;
        RECT 59.375 21.740 63.025 22.160 ;
        RECT 64.655 21.940 64.900 22.160 ;
        RECT 73.340 21.940 74.020 22.160 ;
        RECT 78.575 21.520 82.225 22.160 ;
        RECT 83.375 21.740 93.265 22.160 ;
        RECT 97.775 21.740 101.425 22.160 ;
        RECT 109.295 21.940 116.305 22.160 ;
        RECT 116.975 21.520 120.625 22.160 ;
        RECT 136.175 21.940 138.385 22.160 ;
        RECT 140.975 21.940 144.625 22.160 ;
        RECT 180.860 21.940 181.105 22.160 ;
        RECT 182.255 21.520 184.465 22.160 ;
        RECT 188.015 21.940 190.705 22.160 ;
        RECT 191.420 21.520 193.105 22.160 ;
        RECT 194.255 21.740 194.545 22.160 ;
        RECT 206.255 21.520 209.905 22.160 ;
        RECT 213.980 21.520 214.180 22.160 ;
        RECT 214.895 21.740 218.545 22.160 ;
        RECT 225.455 21.740 229.105 22.160 ;
        RECT 229.775 21.940 233.905 22.160 ;
        RECT 237.020 21.940 239.665 22.160 ;
        RECT 254.255 21.940 278.065 22.160 ;
        RECT 294.575 21.940 312.145 22.160 ;
        RECT 6.095 22.160 54.385 22.360 ;
        RECT 56.540 22.160 64.900 22.360 ;
        RECT 109.295 22.160 138.385 22.360 ;
        RECT 237.020 22.160 278.065 22.360 ;
        RECT 284.975 21.940 290.500 22.360 ;
        RECT 294.575 22.160 313.585 22.360 ;
        RECT 73.340 22.160 102.340 22.360 ;
        RECT 140.975 22.160 150.865 22.360 ;
        RECT 188.015 22.160 213.220 22.360 ;
        RECT 213.935 22.160 233.905 22.360 ;
        RECT 64.175 22.360 64.900 22.580 ;
        RECT 73.340 22.360 73.585 22.580 ;
        RECT 92.540 22.360 102.340 22.580 ;
        RECT 115.580 22.360 138.385 22.580 ;
        RECT 140.975 22.360 141.220 22.580 ;
        RECT 147.695 22.360 150.865 22.580 ;
        RECT 162.620 21.940 162.820 22.580 ;
        RECT 171.695 21.940 174.385 22.580 ;
        RECT 180.860 22.160 185.905 22.580 ;
        RECT 188.015 22.360 201.265 22.580 ;
        RECT 212.975 22.360 213.220 22.580 ;
        RECT 213.935 22.360 220.900 22.580 ;
        RECT 227.375 22.360 233.905 22.580 ;
        RECT 237.020 22.360 237.745 22.580 ;
        RECT 287.855 22.360 290.500 22.580 ;
        RECT 294.575 22.360 295.345 22.580 ;
        RECT 45.455 22.360 49.105 22.780 ;
        RECT 60.475 22.360 62.405 22.780 ;
        RECT 64.175 22.580 73.585 22.780 ;
        RECT 80.495 22.360 90.385 22.780 ;
        RECT 104.975 22.580 105.265 22.780 ;
        RECT 110.475 22.360 112.405 22.780 ;
        RECT 160.475 22.580 201.265 22.780 ;
        RECT 250.415 22.360 250.705 22.780 ;
        RECT 255.695 22.360 255.985 22.780 ;
        RECT 273.455 22.360 277.105 22.780 ;
        RECT 287.855 22.580 295.345 22.780 ;
        RECT 10.475 22.360 16.945 22.780 ;
        RECT 92.540 22.580 103.345 22.780 ;
        RECT 115.580 22.580 141.220 22.780 ;
        RECT 147.695 22.580 157.105 22.780 ;
        RECT 212.975 22.580 220.900 22.780 ;
        RECT 227.375 22.580 237.745 22.780 ;
        RECT 10.475 22.780 13.585 23.000 ;
        RECT 15.215 22.780 16.945 23.000 ;
        RECT 45.455 22.780 46.705 23.000 ;
        RECT 72.815 22.780 73.585 23.000 ;
        RECT 87.740 22.780 90.385 23.000 ;
        RECT 92.540 22.780 99.460 23.000 ;
        RECT 100.655 22.780 103.345 23.000 ;
        RECT 104.975 22.780 105.220 23.000 ;
        RECT 136.700 22.780 141.220 23.000 ;
        RECT 147.695 22.780 147.940 23.000 ;
        RECT 156.860 22.780 157.105 23.000 ;
        RECT 160.475 22.780 188.785 23.000 ;
        RECT 210.475 22.360 212.405 23.000 ;
        RECT 212.975 22.780 215.665 23.000 ;
        RECT 220.655 22.780 220.900 23.000 ;
        RECT 227.375 22.780 230.980 23.000 ;
        RECT 234.095 22.780 237.745 23.000 ;
        RECT 250.415 22.780 250.660 23.000 ;
        RECT 255.740 22.780 255.985 23.000 ;
        RECT 260.475 22.360 262.405 23.000 ;
        RECT 273.455 22.780 275.665 23.000 ;
        RECT 287.855 22.780 294.865 23.000 ;
        RECT 304.175 22.360 312.405 23.000 ;
        RECT 19.055 23.000 32.785 23.200 ;
        RECT 156.860 23.000 188.785 23.200 ;
        RECT 190.895 22.780 193.585 23.200 ;
        RECT 195.695 22.780 198.865 23.200 ;
        RECT 220.655 23.000 230.980 23.200 ;
        RECT 234.095 23.000 244.420 23.200 ;
        RECT 245.615 23.000 250.660 23.200 ;
        RECT 282.620 23.000 294.865 23.200 ;
        RECT 301.775 23.000 318.385 23.200 ;
        RECT 87.740 23.000 99.460 23.200 ;
        RECT 136.700 23.000 147.940 23.200 ;
        RECT 255.740 23.000 275.665 23.200 ;
        RECT 3.695 23.000 13.585 23.420 ;
        RECT 15.215 23.000 17.905 23.420 ;
        RECT 19.055 23.200 28.465 23.420 ;
        RECT 44.015 23.000 46.705 23.420 ;
        RECT 72.815 23.000 75.505 23.420 ;
        RECT 82.415 22.780 85.105 23.420 ;
        RECT 99.260 23.200 99.460 23.420 ;
        RECT 100.655 23.000 105.220 23.420 ;
        RECT 147.215 23.200 147.940 23.420 ;
        RECT 198.095 23.200 198.865 23.420 ;
        RECT 208.175 23.000 215.665 23.420 ;
        RECT 226.895 23.200 230.980 23.420 ;
        RECT 246.095 23.200 250.660 23.420 ;
        RECT 274.895 23.200 275.665 23.420 ;
        RECT 277.295 23.000 279.985 23.420 ;
        RECT 3.215 23.420 28.465 23.620 ;
        RECT 41.615 23.420 47.665 23.620 ;
        RECT 70.415 23.420 76.465 23.620 ;
        RECT 89.615 23.200 95.665 23.620 ;
        RECT 99.260 23.420 109.105 23.620 ;
        RECT 118.415 23.420 124.465 23.620 ;
        RECT 128.015 23.420 134.065 23.620 ;
        RECT 137.615 23.200 143.665 23.620 ;
        RECT 147.215 23.420 153.265 23.620 ;
        RECT 161.135 23.200 165.265 23.620 ;
        RECT 226.895 23.420 232.945 23.620 ;
        RECT 236.495 23.200 242.545 23.620 ;
        RECT 246.095 23.420 251.665 23.620 ;
        RECT 255.740 23.200 261.745 23.620 ;
        RECT 274.895 23.420 280.945 23.620 ;
        RECT 284.495 23.200 290.545 23.620 ;
        RECT 303.695 23.200 309.745 23.620 ;
        RECT 198.095 23.420 204.145 23.620 ;
        RECT 207.695 23.420 217.540 23.620 ;
        RECT 3.215 23.620 7.825 23.840 ;
        RECT 41.615 23.620 46.660 23.840 ;
        RECT 63.695 23.420 65.905 23.840 ;
        RECT 80.015 23.420 86.065 23.840 ;
        RECT 87.740 23.200 87.940 23.840 ;
        RECT 89.615 23.620 94.225 23.840 ;
        RECT 128.015 23.620 132.625 23.840 ;
        RECT 147.215 23.620 151.825 23.840 ;
        RECT 163.055 23.620 165.265 23.840 ;
        RECT 181.295 23.200 183.985 23.840 ;
        RECT 198.095 23.620 202.705 23.840 ;
        RECT 203.375 23.620 204.145 23.840 ;
        RECT 207.695 23.620 214.180 23.840 ;
        RECT 217.295 23.620 217.540 23.840 ;
        RECT 226.895 23.620 231.460 23.840 ;
        RECT 236.495 23.620 241.105 23.840 ;
        RECT 244.220 23.200 244.420 23.840 ;
        RECT 265.775 23.200 266.065 23.840 ;
        RECT 274.895 23.620 275.140 23.840 ;
        RECT 282.620 23.200 282.820 23.840 ;
        RECT 284.495 23.620 289.585 23.840 ;
        RECT 303.695 23.620 304.900 23.840 ;
        RECT 2.735 23.840 7.825 24.040 ;
        RECT 20.975 23.620 21.265 24.040 ;
        RECT 103.055 23.620 106.225 24.040 ;
        RECT 107.375 23.620 107.665 24.040 ;
        RECT 120.815 23.620 123.505 24.040 ;
        RECT 126.575 23.840 126.865 24.040 ;
        RECT 140.015 23.620 142.705 24.040 ;
        RECT 145.775 23.840 146.065 24.040 ;
        RECT 158.255 23.840 158.545 24.040 ;
        RECT 178.415 23.840 184.465 24.040 ;
        RECT 203.375 23.840 214.180 24.040 ;
        RECT 235.055 23.840 235.345 24.040 ;
        RECT 258.095 23.620 260.785 24.040 ;
        RECT 263.855 23.840 264.145 24.040 ;
        RECT 276.335 23.620 280.465 24.040 ;
        RECT 292.655 23.840 292.945 24.040 ;
        RECT 35.420 23.840 46.660 24.040 ;
        RECT 51.215 23.840 69.265 24.040 ;
        RECT 79.100 23.840 88.465 24.040 ;
        RECT 163.055 23.840 177.220 24.040 ;
        RECT 188.495 23.840 196.945 24.040 ;
        RECT 217.295 23.840 223.780 24.040 ;
        RECT 226.415 23.840 231.460 24.040 ;
        RECT 265.295 23.840 275.140 24.040 ;
        RECT 282.620 23.840 289.585 24.040 ;
        RECT 295.055 23.840 301.060 24.040 ;
        RECT 5.135 24.040 7.825 24.260 ;
        RECT 11.900 23.620 12.625 24.260 ;
        RECT 21.020 24.040 21.265 24.260 ;
        RECT 21.935 23.620 27.025 24.260 ;
        RECT 35.420 24.040 35.620 24.260 ;
        RECT 41.135 24.040 46.660 24.260 ;
        RECT 51.215 24.040 51.985 24.260 ;
        RECT 68.540 24.040 69.265 24.260 ;
        RECT 70.895 23.620 75.985 24.260 ;
        RECT 87.740 24.040 88.465 24.260 ;
        RECT 89.135 23.840 94.225 24.260 ;
        RECT 99.260 23.620 99.460 24.260 ;
        RECT 103.055 24.040 105.265 24.260 ;
        RECT 107.420 24.040 107.665 24.260 ;
        RECT 115.580 22.780 115.780 24.260 ;
        RECT 120.815 24.040 123.025 24.260 ;
        RECT 126.620 24.040 126.865 24.260 ;
        RECT 127.535 23.840 132.625 24.260 ;
        RECT 136.700 23.200 136.900 24.260 ;
        RECT 140.015 24.040 142.225 24.260 ;
        RECT 145.820 24.040 146.065 24.260 ;
        RECT 146.735 23.840 151.825 24.260 ;
        RECT 158.300 24.040 158.545 24.260 ;
        RECT 163.055 24.040 167.185 24.260 ;
        RECT 188.495 24.040 190.180 24.260 ;
        RECT 196.220 24.040 196.945 24.260 ;
        RECT 197.615 23.840 202.705 24.260 ;
        RECT 203.375 24.040 204.145 24.260 ;
        RECT 217.295 24.040 217.540 24.260 ;
        RECT 219.215 24.040 223.780 24.260 ;
        RECT 226.415 24.040 227.140 24.260 ;
        RECT 231.215 24.040 231.460 24.260 ;
        RECT 235.100 24.040 235.345 24.260 ;
        RECT 236.015 23.840 241.105 24.260 ;
        RECT 244.220 23.840 244.945 24.260 ;
        RECT 258.095 24.040 260.305 24.260 ;
        RECT 263.900 24.040 264.145 24.260 ;
        RECT 265.295 24.040 271.345 24.260 ;
        RECT 274.895 24.040 275.140 24.260 ;
        RECT 276.815 24.040 280.465 24.260 ;
        RECT 286.415 24.040 289.585 24.260 ;
        RECT 292.700 24.040 292.945 24.260 ;
        RECT 295.055 24.040 300.145 24.260 ;
        RECT 300.815 24.040 301.060 24.260 ;
        RECT 302.255 23.840 304.900 24.260 ;
        RECT 306.095 23.620 308.785 24.260 ;
        RECT 5.135 24.260 9.745 24.460 ;
        RECT 21.020 24.260 28.465 24.460 ;
        RECT 41.135 24.260 51.985 24.460 ;
        RECT 53.135 24.040 57.265 24.460 ;
        RECT 60.335 24.040 66.865 24.460 ;
        RECT 107.420 24.260 111.025 24.460 ;
        RECT 112.175 24.260 115.780 24.460 ;
        RECT 126.620 24.260 134.065 24.460 ;
        RECT 145.820 24.260 153.265 24.460 ;
        RECT 158.300 24.260 167.185 24.460 ;
        RECT 169.340 24.040 170.065 24.460 ;
        RECT 170.735 24.040 174.340 24.460 ;
        RECT 196.220 24.260 204.145 24.460 ;
        RECT 216.815 24.260 217.540 24.460 ;
        RECT 219.215 24.260 227.140 24.460 ;
        RECT 235.100 24.260 242.545 24.460 ;
        RECT 292.700 24.260 300.145 24.460 ;
        RECT 300.815 24.260 309.745 24.460 ;
        RECT 11.900 24.260 17.425 24.460 ;
        RECT 79.100 24.040 84.625 24.460 ;
        RECT 87.740 24.260 95.665 24.460 ;
        RECT 117.935 24.260 123.025 24.460 ;
        RECT 136.700 24.260 142.225 24.460 ;
        RECT 188.060 24.260 190.180 24.460 ;
        RECT 206.780 24.040 212.305 24.460 ;
        RECT 255.215 24.260 260.305 24.460 ;
        RECT 276.815 24.260 280.945 24.460 ;
        RECT 13.295 24.460 17.425 24.680 ;
        RECT 20.060 23.620 20.260 24.680 ;
        RECT 21.020 24.460 22.705 24.680 ;
        RECT 32.495 24.260 35.620 24.680 ;
        RECT 41.135 24.460 41.905 24.680 ;
        RECT 68.540 24.260 76.465 24.680 ;
        RECT 79.100 24.460 80.305 24.680 ;
        RECT 81.455 24.460 84.625 24.680 ;
        RECT 92.015 24.460 95.665 24.680 ;
        RECT 99.215 24.260 99.505 24.680 ;
        RECT 101.135 24.260 105.265 24.680 ;
        RECT 107.420 24.460 109.585 24.680 ;
        RECT 112.175 24.460 113.905 24.680 ;
        RECT 117.935 24.460 118.705 24.680 ;
        RECT 120.335 24.460 123.025 24.680 ;
        RECT 139.535 24.460 142.225 24.680 ;
        RECT 158.300 24.460 159.985 24.680 ;
        RECT 177.020 24.040 177.220 24.680 ;
        RECT 183.740 24.040 183.940 24.680 ;
        RECT 184.655 24.260 185.905 24.680 ;
        RECT 188.060 24.460 188.260 24.680 ;
        RECT 189.980 24.460 190.180 24.680 ;
        RECT 209.615 24.460 212.305 24.680 ;
        RECT 219.695 24.460 227.140 24.680 ;
        RECT 231.215 24.260 231.505 24.680 ;
        RECT 235.100 24.460 241.585 24.680 ;
        RECT 244.220 24.260 252.145 24.680 ;
        RECT 255.215 24.460 255.985 24.680 ;
        RECT 257.615 24.460 260.305 24.680 ;
        RECT 263.900 24.260 271.345 24.680 ;
        RECT 274.895 24.260 275.185 24.680 ;
        RECT 276.815 24.460 279.505 24.680 ;
        RECT 280.175 24.460 280.945 24.680 ;
        RECT 282.620 24.040 284.785 24.680 ;
        RECT 286.415 24.260 290.545 24.680 ;
        RECT 5.615 24.460 8.305 24.880 ;
        RECT 13.295 24.680 19.345 24.880 ;
        RECT 20.060 24.680 22.705 24.880 ;
        RECT 81.455 24.680 85.585 24.880 ;
        RECT 87.740 24.460 89.905 24.880 ;
        RECT 116.015 24.680 118.705 24.880 ;
        RECT 139.535 24.680 143.665 24.880 ;
        RECT 156.815 24.680 159.985 24.880 ;
        RECT 162.095 24.460 164.785 24.880 ;
        RECT 182.735 24.680 188.260 24.880 ;
        RECT 189.980 24.680 194.545 24.880 ;
        RECT 196.220 24.460 198.385 24.880 ;
        RECT 200.495 24.460 203.185 24.880 ;
        RECT 206.780 24.460 207.985 24.880 ;
        RECT 209.615 24.680 213.745 24.880 ;
        RECT 219.695 24.680 232.945 24.880 ;
        RECT 263.855 24.680 272.305 24.880 ;
        RECT 274.415 24.680 279.505 24.880 ;
        RECT 302.255 24.460 309.265 24.880 ;
        RECT 32.060 24.680 41.905 24.880 ;
        RECT 92.015 24.680 109.585 24.880 ;
        RECT 172.700 24.460 174.340 24.880 ;
        RECT 177.020 24.680 181.060 24.880 ;
        RECT 233.615 24.680 241.585 24.880 ;
        RECT 257.615 24.680 261.745 24.880 ;
        RECT 11.900 24.460 12.100 25.100 ;
        RECT 22.460 24.880 22.705 25.100 ;
        RECT 24.815 24.460 27.505 25.100 ;
        RECT 32.060 24.880 32.305 25.100 ;
        RECT 41.660 24.880 41.905 25.100 ;
        RECT 43.535 24.460 47.665 25.100 ;
        RECT 51.215 24.460 51.505 25.100 ;
        RECT 53.615 24.460 56.305 25.100 ;
        RECT 62.255 24.460 66.385 25.100 ;
        RECT 68.540 24.680 80.305 25.100 ;
        RECT 81.935 24.880 85.585 25.100 ;
        RECT 92.015 24.880 95.140 25.100 ;
        RECT 105.935 24.880 109.585 25.100 ;
        RECT 111.215 24.680 113.905 25.100 ;
        RECT 118.460 24.880 118.705 25.100 ;
        RECT 120.335 24.680 124.465 25.100 ;
        RECT 130.415 24.460 133.105 25.100 ;
        RECT 136.700 24.460 137.905 25.100 ;
        RECT 139.535 24.880 143.620 25.100 ;
        RECT 149.615 24.460 152.305 25.100 ;
        RECT 169.340 24.460 169.540 25.100 ;
        RECT 172.700 24.880 172.945 25.100 ;
        RECT 174.140 24.880 174.340 25.100 ;
        RECT 177.020 24.880 179.665 25.100 ;
        RECT 180.860 24.880 181.060 25.100 ;
        RECT 185.180 24.880 188.260 25.100 ;
        RECT 210.575 24.880 213.745 25.100 ;
        RECT 217.340 24.460 217.540 25.100 ;
        RECT 228.380 24.880 232.945 25.100 ;
        RECT 233.615 24.880 237.745 25.100 ;
        RECT 238.460 24.880 241.585 25.100 ;
        RECT 244.220 24.680 255.985 25.100 ;
        RECT 257.615 24.880 258.865 25.100 ;
        RECT 259.535 24.880 261.745 25.100 ;
        RECT 263.855 24.880 266.065 25.100 ;
        RECT 274.895 24.880 279.505 25.100 ;
        RECT 280.175 24.680 291.025 25.100 ;
        RECT 293.615 24.460 298.705 25.100 ;
        RECT 302.255 24.880 306.865 25.100 ;
        RECT 11.900 25.100 12.625 25.300 ;
        RECT 14.735 24.880 18.865 25.300 ;
        RECT 22.460 25.100 32.305 25.300 ;
        RECT 41.660 25.100 80.785 25.300 ;
        RECT 81.935 25.100 86.065 25.300 ;
        RECT 90.095 25.100 95.140 25.300 ;
        RECT 98.735 24.880 101.425 25.300 ;
        RECT 104.015 24.880 104.305 25.300 ;
        RECT 105.935 25.100 114.340 25.300 ;
        RECT 118.460 25.100 143.620 25.300 ;
        RECT 144.335 25.100 152.785 25.300 ;
        RECT 163.055 24.880 163.825 25.300 ;
        RECT 189.980 24.880 191.140 25.300 ;
        RECT 210.575 25.100 214.225 25.300 ;
        RECT 220.700 24.880 222.820 25.300 ;
        RECT 228.380 25.100 237.745 25.300 ;
        RECT 238.460 25.100 258.865 25.300 ;
        RECT 267.695 24.880 270.385 25.300 ;
        RECT 274.895 25.100 306.865 25.300 ;
        RECT 33.935 24.880 38.020 25.300 ;
        RECT 174.140 25.100 179.665 25.300 ;
        RECT 185.180 25.100 188.740 25.300 ;
        RECT 259.535 25.100 266.065 25.300 ;
        RECT 31.535 25.300 32.305 25.520 ;
        RECT 33.935 25.300 36.625 25.520 ;
        RECT 104.015 25.300 104.260 25.520 ;
        RECT 169.295 25.100 169.585 25.520 ;
        RECT 172.655 25.100 172.945 25.520 ;
        RECT 174.140 25.300 174.340 25.520 ;
        RECT 179.420 25.300 179.665 25.520 ;
        RECT 180.860 25.100 182.065 25.520 ;
        RECT 184.220 24.880 184.420 25.520 ;
        RECT 188.540 25.300 188.740 25.520 ;
        RECT 217.295 25.100 217.585 25.520 ;
        RECT 220.700 25.300 220.900 25.520 ;
        RECT 226.460 24.880 226.660 25.520 ;
        RECT 238.940 25.300 258.865 25.520 ;
        RECT 259.535 25.300 263.620 25.520 ;
        RECT 264.815 25.300 266.065 25.520 ;
        RECT 267.695 25.300 269.905 25.520 ;
        RECT 303.215 25.300 306.865 25.520 ;
        RECT 31.535 25.520 36.625 25.720 ;
        RECT 50.735 25.300 55.825 25.720 ;
        RECT 62.300 25.300 64.420 25.720 ;
        RECT 69.935 25.300 75.025 25.720 ;
        RECT 113.135 25.300 113.425 25.720 ;
        RECT 179.420 25.520 184.420 25.720 ;
        RECT 188.540 25.520 189.220 25.720 ;
        RECT 215.375 25.520 220.900 25.720 ;
        RECT 221.615 25.300 221.905 25.720 ;
        RECT 226.460 25.520 227.665 25.720 ;
        RECT 229.295 25.300 231.985 25.720 ;
        RECT 238.940 25.520 263.620 25.720 ;
        RECT 264.815 25.520 269.905 25.720 ;
        RECT 277.340 25.300 280.465 25.720 ;
        RECT 284.015 25.300 289.105 25.720 ;
        RECT 303.215 25.520 308.305 25.720 ;
        RECT 144.380 25.300 145.540 25.720 ;
        RECT 34.415 25.720 36.625 25.940 ;
        RECT 101.615 25.520 104.260 25.940 ;
        RECT 110.300 25.300 112.465 25.940 ;
        RECT 113.135 25.720 113.380 25.940 ;
        RECT 143.420 25.300 143.620 25.940 ;
        RECT 144.380 25.720 144.580 25.940 ;
        RECT 145.340 25.720 145.540 25.940 ;
        RECT 168.815 25.520 174.340 25.940 ;
        RECT 181.775 25.720 184.420 25.940 ;
        RECT 185.180 25.300 185.380 25.940 ;
        RECT 189.020 25.720 189.220 25.940 ;
        RECT 190.940 25.300 191.140 25.940 ;
        RECT 198.095 25.520 203.665 25.940 ;
        RECT 216.815 25.720 220.900 25.940 ;
        RECT 221.615 25.720 221.860 25.940 ;
        RECT 305.615 25.720 308.305 25.940 ;
        RECT 34.415 25.940 37.105 26.140 ;
        RECT 96.815 25.940 104.785 26.140 ;
        RECT 108.335 25.940 113.380 26.140 ;
        RECT 143.420 25.940 144.580 26.140 ;
        RECT 145.340 25.940 174.340 26.140 ;
        RECT 181.775 25.940 185.380 26.140 ;
        RECT 189.020 25.940 208.465 26.140 ;
        RECT 216.815 25.940 221.860 26.140 ;
        RECT 305.615 25.940 309.745 26.140 ;
        RECT 108.335 26.140 112.945 26.360 ;
        RECT 114.140 25.300 114.340 26.360 ;
        RECT 185.135 26.140 185.380 26.360 ;
        RECT 189.020 26.140 194.065 26.360 ;
        RECT 106.415 26.360 112.945 26.560 ;
        RECT 114.140 26.360 116.505 26.560 ;
        RECT 158.735 26.140 166.505 26.560 ;
        RECT 185.135 26.360 194.065 26.560 ;
        RECT 37.820 25.300 38.020 26.780 ;
        RECT 37.775 26.780 38.065 26.980 ;
        RECT 114.140 26.560 114.820 26.980 ;
        RECT 114.575 26.980 114.820 27.200 ;
        RECT 114.575 27.200 114.865 27.400 ;
        RECT 317.135 26.780 320.740 26.980 ;
        RECT 317.135 26.980 318.865 27.200 ;
        RECT 320.540 26.980 320.740 27.200 ;
        RECT 315.695 27.200 318.865 27.400 ;
        RECT 320.540 27.200 322.705 27.400 ;
        RECT 291.695 27.200 301.105 27.620 ;
        RECT 315.695 27.400 316.465 27.620 ;
        RECT 321.020 27.400 322.705 27.620 ;
        RECT 284.015 27.620 316.465 27.820 ;
        RECT 321.020 27.620 325.060 27.820 ;
        RECT 109.775 27.620 113.905 28.040 ;
        RECT 253.295 27.620 259.825 28.040 ;
        RECT 284.015 27.820 284.260 28.040 ;
        RECT 314.255 27.820 316.465 28.040 ;
        RECT 324.860 27.820 325.060 28.040 ;
        RECT 2.735 28.040 284.260 28.240 ;
        RECT 314.255 28.040 318.865 28.240 ;
        RECT 324.860 28.040 328.900 28.240 ;
        RECT 317.615 28.240 318.865 28.460 ;
        RECT 321.020 27.820 321.220 28.460 ;
        RECT 317.615 28.460 321.220 28.660 ;
        RECT 318.095 28.660 320.785 29.300 ;
        RECT 315.695 29.300 321.265 29.500 ;
        RECT 275.855 31.400 282.385 31.600 ;
        RECT 42.575 31.400 47.185 31.820 ;
        RECT 182.255 31.400 184.465 31.820 ;
        RECT 199.055 31.400 203.665 31.820 ;
        RECT 204.815 31.400 214.225 31.820 ;
        RECT 11.900 31.820 274.705 32.020 ;
        RECT 11.900 32.020 18.865 32.240 ;
        RECT 272.975 32.020 274.705 32.240 ;
        RECT 276.860 31.600 277.540 32.240 ;
        RECT 8.015 32.240 18.865 32.440 ;
        RECT 20.495 32.020 28.465 32.440 ;
        RECT 30.095 32.020 38.065 32.440 ;
        RECT 39.695 32.020 47.665 32.440 ;
        RECT 49.295 32.020 57.265 32.440 ;
        RECT 58.895 32.020 66.865 32.440 ;
        RECT 68.495 32.020 76.465 32.440 ;
        RECT 77.615 32.020 86.065 32.440 ;
        RECT 89.615 32.020 95.665 32.440 ;
        RECT 97.295 32.020 105.265 32.440 ;
        RECT 108.815 32.020 114.865 32.440 ;
        RECT 118.415 32.020 124.465 32.440 ;
        RECT 126.095 32.020 134.065 32.440 ;
        RECT 135.695 32.020 143.665 32.440 ;
        RECT 145.295 32.020 153.265 32.440 ;
        RECT 157.775 32.020 165.745 32.440 ;
        RECT 167.375 32.020 175.345 32.440 ;
        RECT 176.975 32.020 184.945 32.440 ;
        RECT 186.575 32.020 194.545 32.440 ;
        RECT 196.175 32.020 204.145 32.440 ;
        RECT 205.775 32.020 213.745 32.440 ;
        RECT 217.295 32.020 223.345 32.440 ;
        RECT 224.975 32.020 232.945 32.440 ;
        RECT 234.575 32.020 242.545 32.440 ;
        RECT 244.175 32.020 252.145 32.440 ;
        RECT 253.775 32.020 261.745 32.440 ;
        RECT 263.855 32.020 271.345 32.440 ;
        RECT 272.975 32.240 280.945 32.440 ;
        RECT 314.255 32.240 318.865 32.440 ;
        RECT 274.415 32.440 280.945 32.660 ;
        RECT 282.575 32.240 290.545 32.660 ;
        RECT 292.655 32.240 300.145 32.660 ;
        RECT 302.255 32.240 309.745 32.660 ;
        RECT 314.255 32.440 316.465 32.660 ;
        RECT 9.935 32.440 12.580 32.860 ;
        RECT 274.415 32.660 316.465 32.860 ;
        RECT 164.575 33.920 166.505 34.120 ;
        RECT 279.695 35.180 316.465 35.380 ;
        RECT 279.695 35.380 279.940 35.600 ;
        RECT 314.255 35.380 316.465 35.600 ;
        RECT 8.015 35.600 279.940 35.800 ;
        RECT 314.255 35.600 318.865 35.800 ;
        RECT 229.775 38.960 239.665 39.380 ;
        RECT 12.380 39.380 284.305 39.580 ;
        RECT 12.380 39.580 12.625 39.800 ;
        RECT 2.735 39.800 12.625 40.000 ;
        RECT 23.855 39.580 28.465 40.000 ;
        RECT 33.455 39.580 38.065 40.000 ;
        RECT 43.055 39.580 47.665 40.000 ;
        RECT 52.655 39.580 57.265 40.000 ;
        RECT 71.855 39.580 76.465 40.000 ;
        RECT 81.455 39.580 86.065 40.000 ;
        RECT 91.055 39.580 95.665 40.000 ;
        RECT 101.135 39.580 105.265 40.000 ;
        RECT 119.855 39.580 124.465 40.000 ;
        RECT 189.935 39.580 194.545 40.000 ;
        RECT 199.535 39.580 204.145 40.000 ;
        RECT 218.735 39.580 223.345 40.000 ;
        RECT 247.535 39.580 252.145 40.000 ;
        RECT 257.135 39.580 261.745 40.000 ;
        RECT 266.735 39.580 271.345 40.000 ;
        RECT 110.255 39.580 114.865 40.220 ;
        RECT 119.855 40.000 121.585 40.220 ;
        RECT 129.455 39.580 134.065 40.220 ;
        RECT 139.055 39.580 143.665 40.220 ;
        RECT 148.655 39.580 153.265 40.220 ;
        RECT 157.295 39.580 157.740 40.220 ;
        RECT 161.135 39.580 165.745 40.220 ;
        RECT 180.335 39.580 184.945 40.220 ;
        RECT 228.335 39.580 232.945 40.220 ;
        RECT 237.935 39.580 242.545 40.220 ;
        RECT 4.655 40.000 9.265 40.420 ;
        RECT 105.935 40.220 121.585 40.420 ;
        RECT 226.895 40.220 246.865 40.420 ;
        RECT 128.015 40.220 188.785 40.420 ;
        RECT 4.655 40.420 5.425 40.640 ;
        RECT 112.175 40.420 121.585 40.640 ;
        RECT 128.015 40.420 130.225 40.640 ;
        RECT 187.055 40.420 188.785 40.640 ;
        RECT 1.775 40.640 5.425 40.840 ;
        RECT 107.375 40.420 111.025 40.840 ;
        RECT 126.575 40.640 130.225 40.840 ;
        RECT 145.775 40.420 149.425 40.840 ;
        RECT 196.655 40.640 200.305 40.840 ;
        RECT 230.255 40.420 232.945 40.840 ;
        RECT 235.055 40.420 238.705 40.840 ;
        RECT 112.175 40.640 122.020 40.840 ;
        RECT 187.055 40.640 190.660 40.840 ;
        RECT 200.975 40.640 211.300 40.840 ;
        RECT 3.740 40.840 5.425 41.060 ;
        RECT 30.575 40.640 34.225 41.060 ;
        RECT 40.175 40.640 43.825 41.060 ;
        RECT 49.775 40.640 53.425 41.060 ;
        RECT 62.255 40.640 66.865 41.060 ;
        RECT 68.975 40.640 72.625 41.060 ;
        RECT 78.575 40.640 81.265 41.060 ;
        RECT 88.175 40.640 91.825 41.060 ;
        RECT 97.775 40.640 101.905 41.060 ;
        RECT 109.775 40.840 111.025 41.060 ;
        RECT 112.175 40.840 119.665 41.060 ;
        RECT 128.495 40.840 130.225 41.060 ;
        RECT 136.175 40.420 139.825 41.060 ;
        RECT 145.775 40.840 147.985 41.060 ;
        RECT 158.255 40.420 161.905 41.060 ;
        RECT 177.455 40.420 181.105 41.060 ;
        RECT 187.055 40.840 189.265 41.060 ;
        RECT 190.415 40.840 190.660 41.060 ;
        RECT 198.575 40.840 200.305 41.060 ;
        RECT 200.975 40.840 208.465 41.060 ;
        RECT 211.100 40.840 211.300 41.060 ;
        RECT 215.855 40.640 219.505 41.060 ;
        RECT 237.455 40.840 238.705 41.060 ;
        RECT 263.855 40.640 267.505 41.060 ;
        RECT 25.295 41.060 106.225 41.260 ;
        RECT 109.775 41.060 119.665 41.260 ;
        RECT 198.575 41.060 208.465 41.260 ;
        RECT 211.100 41.060 230.065 41.260 ;
        RECT 237.455 41.060 240.100 41.260 ;
        RECT 246.095 41.060 252.145 41.260 ;
        RECT 259.055 41.060 268.945 41.260 ;
        RECT 3.740 41.060 13.540 41.260 ;
        RECT 150.095 41.060 189.265 41.260 ;
        RECT 3.740 41.260 3.985 41.480 ;
        RECT 121.820 40.840 122.020 41.480 ;
        RECT 128.495 41.060 147.985 41.480 ;
        RECT 150.095 41.260 150.865 41.480 ;
        RECT 188.495 41.260 189.265 41.480 ;
        RECT 190.415 41.060 190.705 41.480 ;
        RECT 198.575 41.260 207.985 41.480 ;
        RECT 211.100 41.260 211.300 41.480 ;
        RECT 239.855 41.260 240.100 41.480 ;
        RECT 246.095 41.260 249.700 41.480 ;
        RECT 268.175 41.260 268.945 41.480 ;
        RECT 3.695 41.480 3.985 41.680 ;
        RECT 114.575 41.260 116.505 41.680 ;
        RECT 160.175 41.260 163.300 41.680 ;
        RECT 164.575 41.260 166.505 41.680 ;
        RECT 188.495 41.480 207.985 41.680 ;
        RECT 210.575 41.480 211.300 41.680 ;
        RECT 214.575 41.260 216.505 41.680 ;
        RECT 239.855 41.480 249.700 41.680 ;
        RECT 264.575 41.260 266.505 41.680 ;
        RECT 121.775 41.480 150.865 41.680 ;
        RECT 222.620 41.260 227.185 41.680 ;
        RECT 268.175 41.480 281.905 41.680 ;
        RECT 284.495 41.480 294.340 41.680 ;
        RECT 13.340 41.260 13.540 41.900 ;
        RECT 14.575 41.480 16.505 41.900 ;
        RECT 64.575 41.260 66.505 41.900 ;
        RECT 88.175 41.260 89.905 41.900 ;
        RECT 121.775 41.680 131.140 41.900 ;
        RECT 147.695 41.680 150.865 41.900 ;
        RECT 160.175 41.680 160.420 41.900 ;
        RECT 206.255 41.680 207.985 41.900 ;
        RECT 214.940 41.680 216.505 41.900 ;
        RECT 222.620 41.680 222.820 41.900 ;
        RECT 225.455 41.680 227.185 41.900 ;
        RECT 249.455 41.680 249.700 41.900 ;
        RECT 268.175 41.680 270.385 41.900 ;
        RECT 275.375 41.680 281.905 41.900 ;
        RECT 284.495 41.680 285.265 41.900 ;
        RECT 294.095 41.680 294.340 41.900 ;
        RECT 113.615 41.900 113.905 42.100 ;
        RECT 116.975 41.900 120.625 42.100 ;
        RECT 147.695 41.900 160.420 42.100 ;
        RECT 167.855 41.900 171.505 42.100 ;
        RECT 206.255 41.900 209.905 42.100 ;
        RECT 214.940 41.900 222.820 42.100 ;
        RECT 225.455 41.900 229.105 42.100 ;
        RECT 244.655 41.680 248.305 42.100 ;
        RECT 267.695 41.900 270.385 42.100 ;
        RECT 294.095 41.900 314.065 42.100 ;
        RECT 13.295 41.900 99.985 42.100 ;
        RECT 121.295 41.900 131.140 42.100 ;
        RECT 249.455 41.900 259.345 42.100 ;
        RECT 275.375 41.900 285.265 42.100 ;
        RECT 13.295 42.100 17.425 42.320 ;
        RECT 98.735 42.100 99.985 42.320 ;
        RECT 113.660 42.100 113.905 42.320 ;
        RECT 117.935 42.100 120.625 42.320 ;
        RECT 121.295 42.100 123.025 42.320 ;
        RECT 168.815 42.100 171.505 42.320 ;
        RECT 207.215 42.100 209.905 42.320 ;
        RECT 214.940 42.100 215.185 42.320 ;
        RECT 226.415 42.100 229.105 42.320 ;
        RECT 245.615 42.100 248.305 42.320 ;
        RECT 249.455 42.100 250.705 42.320 ;
        RECT 255.215 42.100 259.345 42.320 ;
        RECT 267.695 42.100 269.905 42.320 ;
        RECT 275.375 42.100 279.505 42.320 ;
        RECT 284.015 42.100 285.265 42.320 ;
        RECT 294.095 42.100 298.705 42.320 ;
        RECT 11.375 42.320 11.665 42.520 ;
        RECT 19.055 42.100 29.905 42.520 ;
        RECT 41.135 42.100 46.225 42.520 ;
        RECT 50.735 42.100 55.825 42.520 ;
        RECT 59.375 42.100 59.665 42.520 ;
        RECT 60.335 42.100 65.425 42.520 ;
        RECT 66.575 42.100 68.305 42.520 ;
        RECT 69.935 42.100 75.025 42.520 ;
        RECT 79.535 42.100 84.625 42.520 ;
        RECT 12.335 42.320 17.425 42.520 ;
        RECT 31.535 42.100 36.625 42.520 ;
        RECT 117.935 42.320 123.025 42.520 ;
        RECT 2.735 42.320 7.825 42.740 ;
        RECT 11.420 42.520 11.665 42.740 ;
        RECT 12.335 42.520 15.025 42.740 ;
        RECT 15.695 42.520 17.425 42.740 ;
        RECT 22.415 42.520 29.905 42.740 ;
        RECT 31.535 42.520 32.260 42.740 ;
        RECT 34.415 42.520 36.625 42.740 ;
        RECT 44.015 42.520 46.225 42.740 ;
        RECT 53.615 42.520 55.825 42.740 ;
        RECT 59.420 42.520 59.665 42.740 ;
        RECT 60.335 42.520 63.025 42.740 ;
        RECT 82.415 42.520 84.625 42.740 ;
        RECT 98.735 42.320 103.825 42.740 ;
        RECT 104.495 42.320 112.465 42.740 ;
        RECT 113.660 42.320 114.865 42.740 ;
        RECT 117.935 42.520 118.705 42.740 ;
        RECT 119.375 42.520 123.025 42.740 ;
        RECT 130.940 42.100 131.140 42.740 ;
        RECT 137.135 42.320 142.225 42.740 ;
        RECT 150.095 42.100 150.385 42.740 ;
        RECT 168.815 42.320 173.905 42.740 ;
        RECT 174.575 42.320 185.425 42.740 ;
        RECT 188.015 42.320 193.105 42.740 ;
        RECT 193.775 42.320 201.265 42.740 ;
        RECT 207.215 42.320 212.305 42.740 ;
        RECT 214.895 42.320 215.185 42.740 ;
        RECT 215.855 42.100 217.585 42.740 ;
        RECT 226.415 42.320 237.745 42.740 ;
        RECT 239.375 42.320 243.025 42.740 ;
        RECT 245.615 42.320 250.705 42.740 ;
        RECT 255.215 42.320 260.305 42.740 ;
        RECT 264.815 42.320 269.905 42.740 ;
        RECT 274.415 42.320 279.505 42.740 ;
        RECT 284.015 42.320 289.105 42.740 ;
        RECT 293.615 42.320 298.705 42.740 ;
        RECT 303.215 42.100 308.305 42.740 ;
        RECT 0.335 42.740 9.265 42.940 ;
        RECT 22.415 42.740 32.260 42.940 ;
        RECT 117.020 42.740 118.705 42.940 ;
        RECT 130.895 42.740 313.105 42.940 ;
        RECT 89.660 42.740 115.300 42.940 ;
        RECT 6.575 42.940 9.265 43.160 ;
        RECT 11.420 42.740 15.025 43.160 ;
        RECT 15.695 42.740 17.905 43.160 ;
        RECT 32.015 42.940 32.260 43.160 ;
        RECT 34.415 42.740 37.105 43.160 ;
        RECT 44.015 42.740 46.705 43.160 ;
        RECT 53.615 42.740 56.305 43.160 ;
        RECT 59.420 42.740 63.025 43.160 ;
        RECT 82.415 42.740 85.105 43.160 ;
        RECT 89.660 42.940 89.905 43.160 ;
        RECT 117.020 42.940 117.265 43.160 ;
        RECT 119.375 42.740 128.305 43.160 ;
        RECT 130.895 42.940 133.105 43.160 ;
        RECT 32.015 43.160 89.905 43.360 ;
        RECT 99.215 42.940 110.065 43.360 ;
        RECT 118.895 43.160 128.785 43.360 ;
        RECT 188.975 42.940 198.865 43.360 ;
        RECT 208.175 42.940 232.420 43.360 ;
        RECT 242.735 42.940 268.465 43.360 ;
        RECT 284.495 42.940 284.785 43.360 ;
        RECT 287.375 42.940 312.145 43.360 ;
        RECT 274.895 42.940 280.465 43.360 ;
        RECT 6.575 43.160 18.385 43.580 ;
        RECT 24.815 42.940 27.505 43.580 ;
        RECT 92.015 42.940 94.705 43.580 ;
        RECT 111.215 42.940 113.905 43.580 ;
        RECT 115.100 42.940 115.300 43.580 ;
        RECT 116.975 43.160 117.265 43.580 ;
        RECT 118.895 43.360 119.140 43.580 ;
        RECT 130.415 43.160 133.105 43.580 ;
        RECT 149.615 42.940 152.305 43.580 ;
        RECT 162.095 42.940 164.785 43.580 ;
        RECT 172.655 42.940 172.945 43.580 ;
        RECT 181.295 42.940 183.985 43.580 ;
        RECT 200.495 42.940 203.185 43.580 ;
        RECT 228.815 43.360 232.420 43.580 ;
        RECT 238.895 42.940 241.585 43.580 ;
        RECT 267.215 43.360 268.465 43.580 ;
        RECT 269.135 42.940 271.780 43.580 ;
        RECT 274.895 43.360 275.620 43.580 ;
        RECT 276.815 43.360 280.465 43.580 ;
        RECT 287.375 43.360 290.545 43.580 ;
        RECT 3.215 43.580 3.505 43.780 ;
        RECT 6.095 43.580 18.865 43.780 ;
        RECT 24.335 43.580 28.465 43.780 ;
        RECT 110.735 43.580 119.140 43.780 ;
        RECT 120.335 43.360 124.465 43.780 ;
        RECT 129.935 43.580 134.065 43.780 ;
        RECT 149.135 43.580 153.265 43.780 ;
        RECT 171.215 43.580 175.345 43.780 ;
        RECT 180.815 43.580 184.945 43.780 ;
        RECT 190.415 43.360 194.545 43.780 ;
        RECT 200.015 43.580 204.145 43.780 ;
        RECT 219.215 43.360 223.345 43.780 ;
        RECT 228.815 43.580 232.945 43.780 ;
        RECT 238.415 43.580 242.545 43.780 ;
        RECT 209.615 43.360 217.585 43.780 ;
        RECT 255.740 43.360 265.585 43.780 ;
        RECT 3.260 43.780 3.505 44.000 ;
        RECT 6.095 43.780 13.540 44.000 ;
        RECT 24.335 43.780 27.025 44.000 ;
        RECT 33.935 43.360 38.065 44.000 ;
        RECT 43.535 43.360 47.665 44.000 ;
        RECT 53.135 43.360 57.265 44.000 ;
        RECT 62.735 43.360 66.865 44.000 ;
        RECT 72.335 43.360 76.465 44.000 ;
        RECT 81.935 43.360 86.065 44.000 ;
        RECT 91.535 43.580 95.665 44.000 ;
        RECT 101.135 43.360 105.265 44.000 ;
        RECT 110.735 43.780 113.425 44.000 ;
        RECT 129.935 43.780 132.625 44.000 ;
        RECT 149.135 43.780 151.825 44.000 ;
        RECT 161.615 43.580 165.745 44.000 ;
        RECT 171.215 43.780 174.865 44.000 ;
        RECT 180.815 43.780 183.505 44.000 ;
        RECT 190.415 43.780 194.065 44.000 ;
        RECT 200.015 43.780 202.705 44.000 ;
        RECT 209.615 43.780 214.180 44.000 ;
        RECT 216.815 43.780 217.585 44.000 ;
        RECT 219.215 43.780 221.905 44.000 ;
        RECT 238.415 43.780 241.105 44.000 ;
        RECT 248.015 43.360 252.145 44.000 ;
        RECT 255.740 43.780 255.985 44.000 ;
        RECT 265.340 43.780 265.585 44.000 ;
        RECT 267.215 43.580 275.620 44.000 ;
        RECT 276.815 43.580 280.945 44.000 ;
        RECT 286.415 43.580 290.545 44.000 ;
        RECT 296.015 43.360 300.145 44.000 ;
        RECT 305.615 43.360 309.745 44.000 ;
        RECT 3.260 44.000 13.540 44.200 ;
        RECT 21.935 44.000 27.025 44.200 ;
        RECT 29.615 44.000 106.225 44.200 ;
        RECT 108.335 44.000 113.425 44.200 ;
        RECT 127.535 44.000 132.625 44.200 ;
        RECT 159.215 44.000 174.865 44.200 ;
        RECT 178.415 44.000 183.505 44.200 ;
        RECT 185.135 44.000 194.065 44.200 ;
        RECT 216.815 44.000 221.905 44.200 ;
        RECT 236.015 44.000 241.105 44.200 ;
        RECT 246.095 44.000 255.985 44.200 ;
        RECT 256.655 43.780 263.185 44.200 ;
        RECT 265.340 44.000 313.585 44.200 ;
        RECT 13.340 44.200 13.540 44.420 ;
        RECT 14.300 43.780 14.500 44.420 ;
        RECT 23.375 44.200 27.025 44.420 ;
        RECT 146.735 44.000 151.825 44.420 ;
        RECT 179.855 44.200 183.505 44.420 ;
        RECT 197.615 44.000 202.705 44.420 ;
        RECT 207.695 44.000 214.180 44.420 ;
        RECT 218.255 44.200 221.905 44.420 ;
        RECT 5.180 44.200 8.740 44.620 ;
        RECT 13.340 44.420 19.345 44.620 ;
        RECT 35.855 44.200 38.545 44.620 ;
        RECT 88.700 44.200 94.660 44.620 ;
        RECT 101.660 44.200 102.865 44.620 ;
        RECT 144.815 44.420 152.785 44.620 ;
        RECT 160.655 44.200 160.945 44.620 ;
        RECT 179.855 44.420 184.465 44.620 ;
        RECT 195.215 44.420 203.665 44.620 ;
        RECT 204.335 44.420 214.225 44.620 ;
        RECT 218.255 44.420 223.825 44.620 ;
        RECT 277.340 44.200 288.100 44.620 ;
        RECT 23.375 44.420 27.985 44.620 ;
        RECT 13.820 44.620 19.345 44.840 ;
        RECT 23.375 44.620 25.585 44.840 ;
        RECT 26.255 44.620 27.985 44.840 ;
        RECT 160.700 44.620 160.945 44.840 ;
        RECT 162.575 44.200 164.740 44.840 ;
        RECT 277.340 44.620 279.505 44.840 ;
        RECT 13.820 44.840 25.585 45.040 ;
        RECT 26.255 44.840 28.945 45.040 ;
        RECT 160.700 44.840 167.185 45.040 ;
        RECT 219.695 44.620 222.385 45.040 ;
        RECT 277.295 44.840 279.505 45.040 ;
        RECT 160.700 45.040 162.405 45.260 ;
        RECT 160.475 45.260 162.405 45.460 ;
        RECT 8.015 47.360 284.260 47.560 ;
        RECT 314.255 47.360 318.865 47.560 ;
        RECT 284.015 47.560 284.260 47.780 ;
        RECT 314.255 47.560 316.465 47.780 ;
        RECT 284.015 47.780 316.465 47.980 ;
        RECT 164.575 49.040 166.505 49.240 ;
        RECT 320.975 49.460 325.585 49.660 ;
        RECT 320.975 49.660 324.145 49.880 ;
        RECT 317.615 49.880 324.145 50.080 ;
        RECT 18.140 50.300 271.780 50.500 ;
        RECT 284.015 50.300 316.465 50.500 ;
        RECT 4.655 50.300 9.745 50.720 ;
        RECT 18.140 50.500 18.865 50.720 ;
        RECT 263.855 50.500 271.780 50.720 ;
        RECT 273.455 50.300 280.900 50.720 ;
        RECT 284.015 50.500 290.545 50.720 ;
        RECT 314.255 50.500 316.465 50.720 ;
        RECT 319.055 50.080 319.345 50.720 ;
        RECT 2.735 50.720 18.865 50.920 ;
        RECT 20.495 50.500 28.465 50.920 ;
        RECT 30.095 50.500 38.065 50.920 ;
        RECT 39.695 50.500 47.665 50.920 ;
        RECT 49.295 50.500 57.265 50.920 ;
        RECT 58.895 50.500 66.865 50.920 ;
        RECT 68.015 50.500 76.465 50.920 ;
        RECT 78.095 50.500 86.065 50.920 ;
        RECT 88.655 50.500 95.665 50.920 ;
        RECT 97.775 50.500 105.265 50.920 ;
        RECT 107.855 50.500 114.865 50.920 ;
        RECT 116.975 50.500 124.465 50.920 ;
        RECT 126.095 50.500 134.065 50.920 ;
        RECT 135.695 50.500 143.665 50.920 ;
        RECT 145.295 50.500 153.265 50.920 ;
        RECT 157.775 50.500 165.745 50.920 ;
        RECT 167.375 50.500 175.345 50.920 ;
        RECT 176.975 50.500 184.945 50.920 ;
        RECT 187.055 50.500 194.545 50.920 ;
        RECT 196.175 50.500 204.145 50.920 ;
        RECT 205.775 50.500 213.745 50.920 ;
        RECT 217.295 50.500 223.345 50.920 ;
        RECT 224.975 50.500 232.945 50.920 ;
        RECT 234.575 50.500 242.545 50.920 ;
        RECT 244.175 50.500 252.145 50.920 ;
        RECT 253.775 50.500 261.745 50.920 ;
        RECT 263.855 50.720 280.945 50.920 ;
        RECT 282.575 50.720 290.545 50.920 ;
        RECT 292.175 50.500 300.145 50.920 ;
        RECT 302.255 50.500 309.745 50.920 ;
        RECT 314.255 50.720 321.265 50.920 ;
        RECT 234.575 50.920 242.065 51.140 ;
        RECT 280.220 50.920 280.945 51.140 ;
        RECT 282.575 50.920 284.305 51.140 ;
        RECT 319.055 50.920 321.265 51.140 ;
        RECT 7.055 50.920 18.820 51.340 ;
        RECT 233.135 51.140 242.065 51.340 ;
        RECT 280.220 51.140 284.305 51.340 ;
        RECT 319.055 51.140 326.065 51.340 ;
        RECT 7.055 51.340 9.265 51.560 ;
        RECT 1.295 51.560 9.265 51.760 ;
        RECT 8.015 54.920 279.940 55.120 ;
        RECT 314.255 54.920 318.865 55.120 ;
        RECT 279.695 55.120 279.940 55.340 ;
        RECT 314.255 55.120 316.465 55.340 ;
        RECT 279.695 55.340 316.465 55.540 ;
        RECT 164.575 56.600 166.505 56.800 ;
        RECT 164.575 64.160 166.505 64.360 ;
        RECT 114.140 55.760 114.865 55.960 ;
        RECT 114.140 55.960 114.340 56.600 ;
        RECT 114.140 56.600 116.505 56.800 ;
        RECT 150.575 57.860 157.540 58.060 ;
        RECT 14.255 57.860 18.865 58.280 ;
        RECT 114.140 56.800 114.340 58.280 ;
        RECT 150.575 58.060 153.265 58.280 ;
        RECT 157.295 58.060 157.540 58.280 ;
        RECT 8.015 58.280 31.780 58.480 ;
        RECT 117.980 58.280 127.825 58.480 ;
        RECT 207.260 58.280 217.105 58.480 ;
        RECT 31.535 58.480 31.780 58.700 ;
        RECT 33.455 58.280 38.065 58.700 ;
        RECT 43.055 58.280 47.665 58.700 ;
        RECT 52.655 58.280 57.265 58.700 ;
        RECT 71.855 58.280 76.465 58.700 ;
        RECT 81.935 58.280 86.065 58.700 ;
        RECT 91.055 58.280 95.665 58.700 ;
        RECT 109.775 58.280 114.865 58.700 ;
        RECT 117.980 58.480 118.225 58.700 ;
        RECT 127.580 58.480 127.825 58.700 ;
        RECT 129.455 58.280 134.065 58.700 ;
        RECT 139.055 58.280 143.665 58.700 ;
        RECT 148.655 58.280 153.265 58.700 ;
        RECT 157.295 58.280 163.345 58.700 ;
        RECT 170.735 58.280 175.345 58.700 ;
        RECT 180.335 58.280 184.945 58.700 ;
        RECT 199.535 58.280 204.145 58.700 ;
        RECT 207.260 58.480 207.505 58.700 ;
        RECT 216.860 58.480 217.105 58.700 ;
        RECT 218.735 58.280 223.345 58.700 ;
        RECT 228.335 58.280 232.945 58.700 ;
        RECT 237.935 58.280 242.545 58.700 ;
        RECT 247.535 58.280 252.145 58.700 ;
        RECT 257.135 58.280 261.745 58.700 ;
        RECT 23.855 58.480 28.465 58.900 ;
        RECT 31.535 58.700 118.225 58.900 ;
        RECT 127.580 58.700 207.505 58.900 ;
        RECT 216.860 58.700 284.305 58.900 ;
        RECT 86.255 58.900 118.225 59.120 ;
        RECT 127.580 58.900 131.665 59.120 ;
        RECT 86.255 59.120 131.665 59.320 ;
        RECT 147.215 58.900 169.585 59.320 ;
        RECT 270.575 58.900 278.065 59.320 ;
        RECT 86.255 59.320 86.500 59.540 ;
        RECT 167.855 59.320 169.585 59.540 ;
        RECT 273.455 59.320 278.065 59.540 ;
        RECT 273.455 59.540 312.145 59.740 ;
        RECT 239.855 59.540 249.700 59.740 ;
        RECT 11.375 59.540 15.025 59.960 ;
        RECT 20.975 59.540 24.625 59.960 ;
        RECT 40.175 59.540 43.825 59.960 ;
        RECT 59.375 59.540 63.025 59.960 ;
        RECT 68.975 59.540 72.625 59.960 ;
        RECT 82.460 59.540 86.500 59.960 ;
        RECT 97.775 59.320 101.425 59.960 ;
        RECT 103.055 59.320 103.345 59.960 ;
        RECT 112.655 59.320 115.345 59.960 ;
        RECT 116.975 59.320 120.625 59.960 ;
        RECT 136.175 59.540 139.825 59.960 ;
        RECT 167.855 59.540 171.505 59.960 ;
        RECT 187.055 59.540 190.705 59.960 ;
        RECT 206.255 59.540 209.905 59.960 ;
        RECT 225.455 59.540 229.105 59.960 ;
        RECT 239.855 59.740 240.100 59.960 ;
        RECT 249.455 59.740 249.700 59.960 ;
        RECT 254.255 59.540 257.905 59.960 ;
        RECT 273.455 59.740 277.540 59.960 ;
        RECT 6.575 59.960 26.065 60.160 ;
        RECT 279.260 59.740 284.785 60.160 ;
        RECT 34.940 59.960 44.785 60.160 ;
        RECT 55.100 59.960 150.385 60.160 ;
        RECT 154.895 59.960 218.020 60.160 ;
        RECT 249.455 59.960 277.540 60.160 ;
        RECT 15.695 60.160 26.065 60.380 ;
        RECT 34.940 60.160 35.185 60.380 ;
        RECT 35.855 60.160 44.785 60.380 ;
        RECT 55.100 60.160 55.345 60.380 ;
        RECT 125.660 60.160 150.385 60.380 ;
        RECT 154.895 60.160 155.140 60.380 ;
        RECT 217.775 60.160 218.020 60.380 ;
        RECT 220.655 59.960 240.100 60.380 ;
        RECT 244.655 59.740 248.305 60.380 ;
        RECT 249.455 60.160 256.465 60.380 ;
        RECT 277.295 60.160 277.540 60.380 ;
        RECT 279.260 60.160 279.985 60.380 ;
        RECT 35.855 60.380 55.345 60.580 ;
        RECT 60.475 60.160 62.405 60.580 ;
        RECT 125.660 60.380 155.140 60.580 ;
        RECT 160.475 60.160 162.405 60.580 ;
        RECT 163.055 60.160 201.745 60.580 ;
        RECT 15.695 60.380 35.185 60.580 ;
        RECT 73.295 60.160 83.140 60.580 ;
        RECT 10.475 60.160 12.405 60.800 ;
        RECT 15.695 60.580 15.940 60.800 ;
        RECT 22.895 60.580 35.185 60.800 ;
        RECT 35.855 60.580 51.940 60.800 ;
        RECT 61.340 60.580 62.405 60.800 ;
        RECT 73.295 60.580 75.505 60.800 ;
        RECT 77.660 60.580 83.140 60.800 ;
        RECT 110.475 60.160 112.405 60.800 ;
        RECT 198.140 60.580 201.745 60.800 ;
        RECT 210.475 60.160 212.405 60.800 ;
        RECT 217.775 60.380 256.465 60.800 ;
        RECT 260.475 60.160 262.405 60.800 ;
        RECT 266.735 60.160 271.345 60.800 ;
        RECT 277.295 60.380 279.985 60.800 ;
        RECT 6.095 60.800 15.940 61.000 ;
        RECT 22.895 60.800 51.940 61.000 ;
        RECT 61.340 60.800 71.140 61.000 ;
        RECT 77.660 60.800 119.185 61.000 ;
        RECT 128.060 60.580 147.505 61.000 ;
        RECT 198.140 60.800 294.820 61.000 ;
        RECT 6.095 61.000 8.260 61.220 ;
        RECT 13.340 61.000 15.940 61.220 ;
        RECT 22.895 61.000 23.140 61.220 ;
        RECT 25.775 61.000 51.940 61.220 ;
        RECT 61.340 61.000 61.585 61.220 ;
        RECT 70.895 61.000 71.140 61.220 ;
        RECT 72.815 60.800 75.505 61.220 ;
        RECT 77.660 61.000 109.105 61.220 ;
        RECT 117.500 61.000 119.185 61.220 ;
        RECT 125.660 60.580 125.860 61.220 ;
        RECT 128.060 61.000 128.305 61.220 ;
        RECT 145.340 61.000 147.505 61.220 ;
        RECT 159.740 60.160 159.940 61.220 ;
        RECT 198.140 61.000 198.385 61.220 ;
        RECT 284.495 61.000 294.820 61.220 ;
        RECT 296.495 60.800 299.185 61.220 ;
        RECT 161.135 61.220 165.265 61.420 ;
        RECT 169.295 61.220 198.385 61.420 ;
        RECT 200.975 61.000 213.265 61.420 ;
        RECT 284.495 61.220 313.105 61.420 ;
        RECT 13.340 61.220 23.140 61.420 ;
        RECT 25.775 61.220 61.585 61.420 ;
        RECT 70.895 61.220 109.105 61.420 ;
        RECT 117.500 61.220 128.305 61.420 ;
        RECT 131.375 61.000 141.265 61.420 ;
        RECT 145.340 61.220 150.865 61.420 ;
        RECT 214.940 61.000 220.945 61.420 ;
        RECT 229.775 61.000 249.220 61.420 ;
        RECT 3.695 61.220 8.260 61.640 ;
        RECT 13.340 61.420 13.585 61.640 ;
        RECT 21.935 61.420 23.140 61.640 ;
        RECT 25.775 61.420 27.025 61.640 ;
        RECT 51.215 61.420 61.585 61.640 ;
        RECT 63.695 61.000 65.905 61.640 ;
        RECT 66.575 61.000 68.785 61.640 ;
        RECT 70.895 61.420 78.865 61.640 ;
        RECT 108.860 61.420 109.105 61.640 ;
        RECT 117.500 61.420 126.865 61.640 ;
        RECT 127.535 61.420 128.305 61.640 ;
        RECT 131.375 61.420 132.625 61.640 ;
        RECT 140.015 61.420 141.265 61.640 ;
        RECT 146.735 61.420 150.865 61.640 ;
        RECT 159.740 61.220 160.465 61.640 ;
        RECT 161.135 61.420 164.305 61.640 ;
        RECT 197.615 61.420 198.385 61.640 ;
        RECT 200.975 61.420 202.705 61.640 ;
        RECT 216.815 61.420 220.945 61.640 ;
        RECT 229.775 61.420 231.985 61.640 ;
        RECT 258.575 61.000 260.785 61.640 ;
        RECT 268.175 61.000 270.385 61.640 ;
        RECT 278.735 61.000 280.420 61.640 ;
        RECT 284.495 61.420 289.585 61.640 ;
        RECT 2.735 61.640 13.585 61.840 ;
        RECT 15.215 61.420 17.905 61.840 ;
        RECT 21.935 61.640 27.025 61.840 ;
        RECT 44.015 61.420 46.705 61.840 ;
        RECT 49.775 61.420 50.065 61.840 ;
        RECT 51.215 61.640 78.865 61.840 ;
        RECT 82.415 61.420 85.105 61.840 ;
        RECT 88.175 61.420 88.465 61.840 ;
        RECT 101.615 61.420 104.305 61.840 ;
        RECT 107.375 61.420 107.665 61.840 ;
        RECT 140.015 61.640 142.705 61.840 ;
        RECT 158.255 61.640 158.545 61.840 ;
        RECT 171.695 61.420 174.385 61.840 ;
        RECT 177.455 61.420 177.745 61.840 ;
        RECT 188.015 61.420 188.305 61.840 ;
        RECT 190.895 61.420 193.585 61.840 ;
        RECT 196.655 61.420 196.945 61.840 ;
        RECT 207.215 61.420 207.505 61.840 ;
        RECT 215.855 61.420 216.145 61.840 ;
        RECT 229.295 61.640 231.985 61.840 ;
        RECT 235.055 61.420 235.345 61.840 ;
        RECT 274.415 61.640 274.705 61.840 ;
        RECT 275.375 61.640 280.420 61.840 ;
        RECT 292.655 61.420 292.945 61.840 ;
        RECT 31.580 61.420 35.665 61.840 ;
        RECT 108.860 61.640 126.865 61.840 ;
        RECT 256.175 61.640 271.780 61.840 ;
        RECT 294.095 61.420 303.985 61.840 ;
        RECT 12.335 61.840 13.585 62.060 ;
        RECT 15.215 61.840 17.425 62.060 ;
        RECT 22.415 61.840 27.025 62.060 ;
        RECT 31.580 61.840 32.305 62.060 ;
        RECT 33.935 61.840 35.665 62.060 ;
        RECT 44.015 61.840 46.225 62.060 ;
        RECT 49.820 61.840 50.065 62.060 ;
        RECT 51.215 61.840 57.265 62.060 ;
        RECT 82.415 61.840 84.625 62.060 ;
        RECT 88.220 61.840 88.465 62.060 ;
        RECT 101.615 61.840 103.825 62.060 ;
        RECT 107.420 61.840 107.665 62.060 ;
        RECT 108.860 61.840 114.340 62.060 ;
        RECT 126.620 61.840 126.865 62.060 ;
        RECT 127.535 61.640 132.625 62.060 ;
        RECT 140.015 61.840 142.225 62.060 ;
        RECT 145.340 61.420 146.065 62.060 ;
        RECT 146.735 61.640 151.825 62.060 ;
        RECT 158.300 61.840 158.545 62.060 ;
        RECT 159.215 61.640 164.305 62.060 ;
        RECT 171.695 61.840 173.905 62.060 ;
        RECT 177.500 61.840 177.745 62.060 ;
        RECT 178.415 61.420 183.505 62.060 ;
        RECT 188.060 61.840 188.305 62.060 ;
        RECT 190.895 61.840 193.105 62.060 ;
        RECT 196.700 61.840 196.945 62.060 ;
        RECT 197.615 61.640 202.705 62.060 ;
        RECT 207.260 61.840 207.505 62.060 ;
        RECT 214.940 61.420 215.140 62.060 ;
        RECT 215.900 61.840 216.145 62.060 ;
        RECT 216.815 61.640 221.905 62.060 ;
        RECT 229.295 61.840 231.505 62.060 ;
        RECT 235.100 61.840 235.345 62.060 ;
        RECT 236.015 61.420 241.105 62.060 ;
        RECT 249.020 61.420 249.220 62.060 ;
        RECT 256.175 61.840 260.305 62.060 ;
        RECT 274.460 61.840 274.705 62.060 ;
        RECT 275.375 61.840 279.505 62.060 ;
        RECT 283.055 61.640 289.585 62.060 ;
        RECT 294.095 61.840 298.705 62.060 ;
        RECT 300.380 61.840 303.985 62.060 ;
        RECT 306.095 61.420 308.785 62.060 ;
        RECT 5.135 61.840 8.785 62.260 ;
        RECT 12.335 62.060 17.425 62.260 ;
        RECT 22.415 62.060 32.305 62.260 ;
        RECT 33.935 62.060 38.065 62.260 ;
        RECT 41.135 62.060 46.225 62.260 ;
        RECT 49.820 62.060 57.265 62.260 ;
        RECT 60.335 61.840 65.425 62.260 ;
        RECT 67.580 61.840 76.465 62.260 ;
        RECT 88.220 62.060 95.665 62.260 ;
        RECT 98.735 62.060 103.825 62.260 ;
        RECT 107.420 62.060 114.340 62.260 ;
        RECT 117.980 61.840 123.025 62.260 ;
        RECT 126.620 62.060 134.065 62.260 ;
        RECT 137.135 62.060 142.225 62.260 ;
        RECT 145.340 62.060 153.265 62.260 ;
        RECT 158.300 62.060 167.185 62.260 ;
        RECT 168.815 62.060 173.905 62.260 ;
        RECT 177.500 62.060 184.945 62.260 ;
        RECT 188.060 62.060 193.105 62.260 ;
        RECT 196.700 62.060 204.145 62.260 ;
        RECT 207.260 62.060 212.305 62.260 ;
        RECT 213.935 62.060 215.140 62.260 ;
        RECT 215.900 62.060 223.345 62.260 ;
        RECT 226.415 62.060 231.505 62.260 ;
        RECT 235.100 62.060 242.545 62.260 ;
        RECT 255.215 62.060 260.305 62.260 ;
        RECT 267.215 61.840 271.780 62.260 ;
        RECT 274.460 62.060 279.505 62.260 ;
        RECT 281.180 62.060 290.545 62.260 ;
        RECT 248.975 62.060 254.500 62.260 ;
        RECT 300.380 62.060 309.745 62.260 ;
        RECT 12.815 62.260 17.425 62.480 ;
        RECT 22.415 62.260 22.660 62.480 ;
        RECT 43.535 62.260 46.225 62.480 ;
        RECT 62.255 62.260 65.425 62.480 ;
        RECT 78.620 61.840 78.820 62.480 ;
        RECT 79.535 62.060 84.625 62.480 ;
        RECT 101.135 62.260 103.825 62.480 ;
        RECT 120.335 62.260 123.025 62.480 ;
        RECT 139.535 62.260 142.225 62.480 ;
        RECT 171.215 62.260 173.905 62.480 ;
        RECT 190.415 62.260 193.105 62.480 ;
        RECT 209.615 62.260 212.305 62.480 ;
        RECT 228.815 62.260 231.505 62.480 ;
        RECT 248.975 62.260 252.100 62.480 ;
        RECT 257.615 62.260 260.305 62.480 ;
        RECT 271.580 62.260 271.780 62.480 ;
        RECT 274.460 62.260 275.665 62.480 ;
        RECT 292.700 61.840 292.900 62.480 ;
        RECT 293.615 62.060 298.705 62.480 ;
        RECT 300.380 62.260 300.580 62.480 ;
        RECT 304.655 62.260 309.745 62.480 ;
        RECT 12.815 62.480 22.660 62.680 ;
        RECT 32.975 62.480 33.265 62.680 ;
        RECT 43.535 62.480 47.665 62.680 ;
        RECT 71.375 62.260 73.585 62.680 ;
        RECT 78.620 62.480 86.065 62.680 ;
        RECT 90.575 62.260 90.865 62.680 ;
        RECT 111.215 62.260 114.340 62.680 ;
        RECT 120.335 62.480 124.465 62.680 ;
        RECT 139.535 62.480 143.665 62.680 ;
        RECT 149.615 62.260 152.305 62.680 ;
        RECT 228.815 62.480 232.945 62.680 ;
        RECT 238.895 62.260 241.585 62.680 ;
        RECT 248.015 62.480 252.100 62.680 ;
        RECT 268.175 62.260 270.865 62.680 ;
        RECT 271.580 62.480 275.665 62.680 ;
        RECT 276.335 62.260 279.025 62.680 ;
        RECT 285.455 62.260 290.500 62.680 ;
        RECT 304.655 62.480 313.585 62.680 ;
        RECT 200.495 62.260 203.185 62.680 ;
        RECT 5.615 62.260 8.305 62.900 ;
        RECT 12.815 62.680 13.060 62.900 ;
        RECT 24.815 62.260 27.505 62.900 ;
        RECT 33.020 62.680 33.265 62.900 ;
        RECT 34.415 62.260 37.105 62.900 ;
        RECT 44.495 62.680 47.665 62.900 ;
        RECT 54.095 62.260 54.385 62.900 ;
        RECT 62.255 62.480 66.385 62.900 ;
        RECT 67.580 62.260 67.780 62.900 ;
        RECT 71.420 62.680 73.585 62.900 ;
        RECT 83.375 62.680 86.065 62.900 ;
        RECT 90.620 62.680 90.865 62.900 ;
        RECT 92.015 62.260 94.705 62.900 ;
        RECT 101.135 62.480 105.265 62.900 ;
        RECT 130.415 62.260 133.105 62.900 ;
        RECT 140.975 62.680 143.665 62.900 ;
        RECT 145.340 62.260 145.540 62.900 ;
        RECT 150.095 62.680 152.305 62.900 ;
        RECT 162.095 62.260 164.785 62.900 ;
        RECT 171.215 62.480 175.345 62.900 ;
        RECT 181.295 62.260 183.985 62.900 ;
        RECT 190.415 62.480 194.545 62.900 ;
        RECT 200.495 62.680 201.265 62.900 ;
        RECT 201.935 62.680 203.185 62.900 ;
        RECT 209.615 62.480 213.745 62.900 ;
        RECT 219.695 62.260 222.385 62.900 ;
        RECT 228.815 62.680 230.065 62.900 ;
        RECT 254.300 62.260 254.500 62.900 ;
        RECT 257.615 62.480 261.745 62.900 ;
        RECT 263.855 62.480 266.545 62.900 ;
        RECT 268.175 62.680 268.420 62.900 ;
        RECT 276.815 62.680 279.025 62.900 ;
        RECT 281.180 62.260 281.380 62.900 ;
        RECT 285.500 62.680 290.500 62.900 ;
        RECT 292.700 62.480 300.580 62.900 ;
        RECT 3.215 62.900 13.060 63.100 ;
        RECT 14.735 62.680 18.865 63.100 ;
        RECT 24.335 62.900 28.465 63.100 ;
        RECT 33.020 62.900 38.545 63.100 ;
        RECT 44.495 62.900 67.780 63.100 ;
        RECT 71.420 62.900 75.985 63.100 ;
        RECT 83.375 62.900 86.545 63.100 ;
        RECT 90.620 62.900 95.185 63.100 ;
        RECT 100.175 62.900 105.745 63.100 ;
        RECT 113.615 62.680 114.340 63.100 ;
        RECT 120.815 62.680 123.505 63.100 ;
        RECT 128.975 62.900 134.545 63.100 ;
        RECT 140.975 62.900 145.540 63.100 ;
        RECT 150.095 62.900 201.265 63.100 ;
        RECT 201.935 62.900 230.065 63.100 ;
        RECT 254.300 62.900 268.420 63.100 ;
        RECT 276.815 62.900 281.380 63.100 ;
        RECT 285.500 62.900 300.580 63.100 ;
        RECT 304.700 62.680 309.265 63.100 ;
        RECT 7.055 63.100 11.665 63.520 ;
        RECT 50.735 63.100 55.825 63.520 ;
        RECT 62.300 63.100 67.780 63.520 ;
        RECT 210.140 63.100 214.225 63.520 ;
        RECT 277.775 63.100 281.380 63.520 ;
        RECT 251.900 62.680 252.100 63.740 ;
        RECT 251.855 63.740 252.145 63.940 ;
        RECT 114.140 63.100 114.340 64.160 ;
        RECT 114.140 64.160 116.505 64.360 ;
        RECT 114.140 64.360 114.820 64.780 ;
        RECT 114.575 64.780 114.820 65.000 ;
        RECT 114.575 65.000 114.865 65.200 ;
        RECT 284.015 65.420 316.465 65.620 ;
        RECT 284.015 65.620 284.260 65.840 ;
        RECT 314.255 65.620 316.465 65.840 ;
        RECT 2.735 65.840 284.260 66.040 ;
        RECT 314.255 65.840 318.865 66.040 ;
        RECT 163.535 68.360 167.185 68.560 ;
        RECT 0.815 69.200 8.785 69.400 ;
        RECT 8.015 69.400 8.785 69.620 ;
        RECT 148.175 69.200 152.785 69.620 ;
        RECT 195.695 69.200 203.665 69.620 ;
        RECT 8.015 69.620 284.305 69.820 ;
        RECT 282.575 69.820 284.305 70.040 ;
        RECT 9.935 69.820 18.865 70.240 ;
        RECT 20.495 69.820 28.465 70.240 ;
        RECT 30.575 69.820 38.065 70.240 ;
        RECT 39.695 69.820 47.665 70.240 ;
        RECT 49.295 69.820 57.265 70.240 ;
        RECT 58.895 69.820 66.865 70.240 ;
        RECT 68.495 69.820 76.465 70.240 ;
        RECT 78.095 69.820 86.065 70.240 ;
        RECT 88.175 69.820 95.665 70.240 ;
        RECT 97.295 69.820 105.265 70.240 ;
        RECT 107.375 69.820 114.865 70.240 ;
        RECT 116.975 69.820 124.465 70.240 ;
        RECT 126.095 69.820 134.065 70.240 ;
        RECT 135.695 69.820 143.665 70.240 ;
        RECT 145.295 69.820 153.265 70.240 ;
        RECT 157.775 69.820 165.745 70.240 ;
        RECT 167.375 69.820 175.345 70.240 ;
        RECT 176.975 69.820 184.945 70.240 ;
        RECT 186.575 69.820 194.545 70.240 ;
        RECT 196.175 69.820 204.145 70.240 ;
        RECT 206.255 69.820 213.745 70.240 ;
        RECT 215.855 69.820 223.345 70.240 ;
        RECT 224.975 69.820 232.945 70.240 ;
        RECT 234.575 69.820 242.545 70.240 ;
        RECT 244.175 69.820 252.145 70.240 ;
        RECT 253.775 69.820 261.745 70.240 ;
        RECT 262.895 69.820 271.345 70.240 ;
        RECT 272.975 69.820 280.945 70.240 ;
        RECT 282.575 70.040 290.545 70.240 ;
        RECT 314.255 70.040 318.865 70.240 ;
        RECT 284.015 70.240 290.545 70.460 ;
        RECT 292.175 70.040 300.145 70.460 ;
        RECT 303.695 70.040 309.745 70.460 ;
        RECT 314.255 70.240 316.465 70.460 ;
        RECT 284.015 70.460 316.465 70.660 ;
        RECT 164.575 71.720 166.505 71.920 ;
        RECT 279.695 72.980 316.465 73.180 ;
        RECT 279.695 73.180 279.940 73.400 ;
        RECT 314.255 73.180 316.465 73.400 ;
        RECT 8.015 73.400 279.940 73.600 ;
        RECT 314.255 73.400 318.865 73.600 ;
        RECT 116.975 76.760 121.585 76.960 ;
        RECT 88.175 76.760 92.785 77.180 ;
        RECT 107.375 76.760 111.985 77.180 ;
        RECT 116.975 76.960 118.225 77.180 ;
        RECT 8.015 77.180 118.225 77.380 ;
        RECT 216.860 77.180 284.305 77.380 ;
        RECT 127.580 77.180 207.505 77.380 ;
        RECT 117.980 77.380 118.225 77.600 ;
        RECT 127.580 77.380 127.825 77.600 ;
        RECT 207.260 77.380 207.505 77.600 ;
        RECT 216.860 77.380 217.105 77.600 ;
        RECT 16.655 77.380 18.865 77.800 ;
        RECT 25.775 77.380 28.465 77.800 ;
        RECT 35.375 77.380 38.065 77.800 ;
        RECT 54.575 77.380 57.265 77.800 ;
        RECT 73.775 77.380 76.465 77.800 ;
        RECT 92.975 77.380 95.665 77.800 ;
        RECT 112.175 77.380 114.865 77.800 ;
        RECT 117.980 77.600 127.825 77.800 ;
        RECT 131.375 77.380 134.065 77.800 ;
        RECT 150.575 77.380 153.265 77.800 ;
        RECT 157.295 77.380 157.585 77.800 ;
        RECT 163.055 77.380 165.745 77.800 ;
        RECT 182.255 77.380 184.945 77.800 ;
        RECT 191.855 77.380 194.545 77.800 ;
        RECT 201.455 77.380 204.145 77.800 ;
        RECT 207.260 77.600 217.105 77.800 ;
        RECT 220.655 77.380 223.345 77.800 ;
        RECT 230.255 77.380 232.945 77.800 ;
        RECT 239.855 77.380 242.545 77.800 ;
        RECT 268.655 77.380 271.345 77.800 ;
        RECT 206.255 78.440 210.820 78.640 ;
        RECT 210.620 78.640 210.820 78.860 ;
        RECT 210.620 78.860 213.745 79.060 ;
        RECT 157.340 77.800 157.540 79.280 ;
        RECT 210.620 79.060 210.865 79.280 ;
        RECT 147.695 79.280 160.420 79.480 ;
        RECT 64.575 79.280 66.505 79.700 ;
        RECT 114.575 79.280 116.505 79.700 ;
        RECT 147.695 79.480 148.900 79.700 ;
        RECT 160.175 79.480 160.420 79.700 ;
        RECT 164.575 79.280 166.505 79.700 ;
        RECT 210.575 79.280 210.865 79.700 ;
        RECT 214.575 79.280 216.505 79.700 ;
        RECT 160.175 79.700 170.065 79.900 ;
        RECT 208.175 79.700 256.465 79.900 ;
        RECT 33.455 79.700 148.900 79.900 ;
        RECT 276.335 79.700 286.225 79.900 ;
        RECT 33.455 79.900 36.625 80.120 ;
        RECT 168.815 79.900 170.065 80.120 ;
        RECT 208.175 79.900 212.305 80.120 ;
        RECT 276.335 79.900 279.505 80.120 ;
        RECT 284.015 79.900 286.225 80.120 ;
        RECT 11.375 80.120 11.665 80.320 ;
        RECT 12.335 80.120 17.425 80.320 ;
        RECT 31.535 80.120 36.625 80.320 ;
        RECT 41.135 79.900 46.225 80.320 ;
        RECT 50.735 79.900 55.825 80.320 ;
        RECT 59.375 79.900 59.665 80.320 ;
        RECT 60.335 79.900 65.425 80.320 ;
        RECT 69.935 79.900 75.025 80.320 ;
        RECT 226.415 79.900 231.505 80.320 ;
        RECT 245.615 79.900 250.705 80.320 ;
        RECT 11.420 80.320 11.665 80.540 ;
        RECT 12.335 80.320 15.985 80.540 ;
        RECT 31.535 80.320 33.745 80.540 ;
        RECT 59.420 80.320 59.665 80.540 ;
        RECT 60.335 80.320 63.985 80.540 ;
        RECT 70.895 80.320 75.025 80.540 ;
        RECT 79.535 79.900 84.625 80.540 ;
        RECT 98.735 79.900 103.825 80.540 ;
        RECT 117.935 79.900 123.025 80.540 ;
        RECT 137.135 79.900 142.225 80.540 ;
        RECT 148.700 79.900 148.900 80.540 ;
        RECT 168.815 80.120 173.905 80.540 ;
        RECT 188.015 80.120 193.105 80.540 ;
        RECT 207.215 80.120 212.305 80.540 ;
        RECT 215.855 79.900 217.585 80.540 ;
        RECT 226.415 80.320 228.580 80.540 ;
        RECT 245.615 80.320 247.825 80.540 ;
        RECT 259.055 80.120 261.745 80.540 ;
        RECT 264.815 80.120 269.905 80.540 ;
        RECT 274.415 80.120 279.505 80.540 ;
        RECT 284.015 80.120 289.105 80.540 ;
        RECT 293.615 80.120 298.705 80.540 ;
        RECT 303.215 80.120 308.305 80.540 ;
        RECT 70.895 80.540 147.985 80.740 ;
        RECT 148.655 80.540 228.580 80.740 ;
        RECT 23.855 80.540 33.745 80.740 ;
        RECT 237.980 80.540 247.825 80.740 ;
        RECT 256.175 80.540 313.105 80.740 ;
        RECT 6.575 80.540 8.740 80.960 ;
        RECT 11.420 80.540 15.985 80.960 ;
        RECT 23.855 80.740 24.100 80.960 ;
        RECT 32.495 80.740 33.745 80.960 ;
        RECT 59.420 80.540 63.985 80.960 ;
        RECT 70.895 80.740 71.140 80.960 ;
        RECT 228.335 80.740 228.580 80.960 ;
        RECT 237.980 80.740 238.225 80.960 ;
        RECT 247.580 80.740 247.825 80.960 ;
        RECT 256.175 80.740 257.425 80.960 ;
        RECT 285.935 80.740 313.105 80.960 ;
        RECT 169.775 80.740 179.665 81.160 ;
        RECT 5.615 80.960 24.100 81.380 ;
        RECT 24.815 80.740 27.505 81.380 ;
        RECT 32.495 80.960 71.140 81.380 ;
        RECT 92.015 80.740 94.705 81.380 ;
        RECT 111.215 80.740 113.905 81.380 ;
        RECT 130.415 80.740 133.105 81.380 ;
        RECT 149.615 80.740 152.305 81.380 ;
        RECT 162.095 80.740 164.785 81.380 ;
        RECT 169.775 81.160 171.505 81.380 ;
        RECT 178.895 81.160 179.665 81.380 ;
        RECT 181.295 80.740 183.985 81.380 ;
        RECT 200.495 80.740 203.185 81.380 ;
        RECT 219.695 80.740 222.385 81.380 ;
        RECT 228.335 80.960 238.225 81.380 ;
        RECT 238.895 80.740 241.585 81.380 ;
        RECT 247.580 80.960 257.425 81.380 ;
        RECT 258.095 80.740 260.785 81.380 ;
        RECT 285.935 80.960 313.585 81.380 ;
        RECT 149.135 81.380 171.505 81.580 ;
        RECT 178.895 81.380 314.065 81.580 ;
        RECT 3.215 81.380 147.505 81.580 ;
        RECT 3.215 81.580 7.825 81.800 ;
        RECT 146.735 81.580 147.505 81.800 ;
        RECT 149.135 81.580 151.825 81.800 ;
        RECT 178.895 81.580 183.505 81.800 ;
        RECT 2.735 81.800 7.825 82.000 ;
        RECT 146.735 81.800 151.825 82.000 ;
        RECT 159.215 81.580 164.305 82.000 ;
        RECT 216.815 81.580 221.905 82.000 ;
        RECT 236.015 81.580 241.105 82.000 ;
        RECT 255.215 81.580 260.305 82.000 ;
        RECT 276.815 81.580 312.145 82.000 ;
        RECT 178.415 81.800 183.505 82.000 ;
        RECT 3.695 82.000 7.825 82.220 ;
        RECT 21.935 81.580 27.025 82.220 ;
        RECT 89.135 81.580 94.225 82.220 ;
        RECT 108.335 81.580 113.425 82.220 ;
        RECT 127.535 81.580 132.625 82.220 ;
        RECT 146.735 82.000 149.425 82.220 ;
        RECT 178.415 82.000 179.185 82.220 ;
        RECT 179.855 82.000 183.505 82.220 ;
        RECT 197.615 81.580 202.705 82.220 ;
        RECT 257.135 82.000 260.305 82.220 ;
        RECT 3.695 82.220 32.785 82.420 ;
        RECT 72.380 82.220 149.425 82.420 ;
        RECT 169.340 82.220 179.185 82.420 ;
        RECT 6.095 82.420 32.785 82.640 ;
        RECT 72.380 82.420 72.625 82.640 ;
        RECT 147.215 82.420 149.425 82.640 ;
        RECT 169.340 82.420 169.585 82.640 ;
        RECT 171.215 82.420 179.185 82.640 ;
        RECT 179.855 82.220 208.465 82.640 ;
        RECT 257.135 82.220 276.625 82.640 ;
        RECT 6.095 82.640 72.625 82.840 ;
        RECT 147.215 82.640 169.585 82.840 ;
        RECT 171.215 82.640 277.105 82.840 ;
        RECT 10.475 82.840 12.405 83.260 ;
        RECT 60.475 82.840 62.405 83.260 ;
        RECT 160.475 82.840 162.405 83.260 ;
        RECT 210.475 82.840 212.405 83.260 ;
        RECT 260.475 82.840 262.405 83.260 ;
        RECT 226.940 13.340 234.385 13.760 ;
        RECT 226.940 13.760 265.105 13.960 ;
        RECT 226.940 13.960 227.140 14.180 ;
        RECT 195.695 14.180 227.140 14.380 ;
        RECT 196.175 14.380 204.145 14.800 ;
        RECT 205.775 14.380 213.745 14.800 ;
        RECT 210.475 14.800 212.405 15.220 ;
        RECT 244.655 78.440 249.265 78.640 ;
        RECT 244.175 7.880 252.625 8.080 ;
        RECT 244.175 18.800 251.665 19.000 ;
        RECT 279.215 11.660 302.065 11.860 ;
        RECT 284.015 11.860 288.145 12.280 ;
        RECT 292.220 11.860 293.905 12.280 ;
        RECT 294.575 11.860 301.585 12.280 ;
        RECT 292.220 12.280 292.465 12.500 ;
        RECT 292.175 12.500 292.465 12.700 ;
        RECT 295.055 12.280 295.345 12.700 ;
        RECT 317.615 12.500 321.700 12.700 ;
        RECT 295.100 12.700 295.345 12.920 ;
        RECT 321.500 12.700 321.700 12.920 ;
        RECT 264.815 12.920 274.705 13.120 ;
        RECT 321.500 12.920 328.900 13.120 ;
        RECT 274.460 13.120 274.705 13.340 ;
        RECT 275.375 12.920 280.945 13.340 ;
        RECT 295.100 12.920 300.625 13.340 ;
        RECT 321.500 13.120 322.225 13.340 ;
        RECT 274.460 13.340 301.105 13.540 ;
        RECT 318.095 13.340 322.225 13.540 ;
        RECT 323.420 13.120 326.545 13.540 ;
        RECT 279.740 13.540 301.105 13.760 ;
        RECT 314.255 13.340 316.900 13.760 ;
        RECT 318.095 13.540 318.865 13.760 ;
        RECT 323.420 13.540 323.665 13.760 ;
        RECT 279.740 13.760 318.865 13.960 ;
        RECT 328.175 13.760 328.465 13.960 ;
        RECT 274.895 13.540 279.025 14.180 ;
        RECT 279.740 13.960 280.465 14.180 ;
        RECT 323.375 13.760 323.665 14.180 ;
        RECT 328.175 13.960 328.420 14.180 ;
        RECT 319.055 14.180 328.420 14.380 ;
        RECT 272.975 14.180 280.465 14.380 ;
        RECT 272.975 14.380 276.100 14.600 ;
        RECT 278.735 14.380 280.465 14.600 ;
        RECT 234.095 14.600 276.100 14.800 ;
        RECT 278.735 14.600 281.425 14.800 ;
        RECT 321.935 14.380 328.420 14.800 ;
        RECT 260.475 14.800 262.405 15.220 ;
        RECT 320.015 54.920 326.065 55.120 ;
        RECT 310.475 45.260 312.405 45.460 ;
        RECT 317.615 55.760 324.625 55.960 ;
        RECT 325.775 43.160 328.900 43.360 ;
        RECT 264.575 56.600 266.505 56.800 ;
        RECT 314.575 56.600 316.505 56.800 ;
        RECT 278.735 57.440 280.465 57.640 ;
        RECT 263.855 57.860 267.505 58.060 ;
        RECT 324.335 58.280 328.900 58.480 ;
        RECT 320.975 58.280 322.225 58.480 ;
        RECT 302.255 57.440 305.905 57.860 ;
        RECT 284.015 57.860 316.465 58.060 ;
        RECT 314.255 58.060 316.465 58.280 ;
        RECT 285.935 58.060 290.545 58.480 ;
        RECT 296.015 58.060 300.145 58.480 ;
        RECT 314.255 58.280 318.865 58.480 ;
        RECT 305.135 58.060 309.745 58.700 ;
        RECT 318.095 58.480 318.865 58.700 ;
        RECT 303.695 58.700 313.585 58.900 ;
        RECT 318.095 58.700 320.785 58.900 ;
        RECT 319.055 59.540 320.785 59.740 ;
        RECT 310.475 60.380 312.405 60.580 ;
        RECT 319.535 47.360 326.545 47.560 ;
        RECT 321.455 47.560 326.065 48.200 ;
        RECT 317.615 48.200 328.900 48.400 ;
        RECT 264.575 64.160 266.505 64.360 ;
        RECT 314.575 64.160 316.505 64.360 ;
        RECT 317.615 63.320 328.900 63.520 ;
        RECT 317.615 63.520 318.865 63.740 ;
        RECT 317.135 63.740 318.865 63.940 ;
        RECT 317.615 63.940 318.865 64.160 ;
        RECT 317.615 64.160 320.305 64.360 ;
        RECT 321.020 64.580 323.665 64.780 ;
        RECT 321.020 64.780 321.220 66.260 ;
        RECT 320.015 66.260 321.220 66.460 ;
        RECT 252.815 67.520 259.345 67.720 ;
        RECT 260.475 67.940 262.405 68.140 ;
        RECT 310.475 67.940 312.405 68.140 ;
        RECT 264.575 49.040 266.505 49.240 ;
        RECT 317.615 68.360 328.900 68.560 ;
        RECT 317.135 69.200 322.705 69.400 ;
        RECT 320.975 70.040 322.225 70.240 ;
        RECT 314.575 49.040 316.505 49.240 ;
        RECT 317.615 70.880 324.625 71.080 ;
        RECT 260.475 45.260 262.405 45.460 ;
        RECT 264.575 71.720 266.505 71.920 ;
        RECT 314.575 71.720 316.505 71.920 ;
        RECT 318.095 71.720 320.785 71.920 ;
        RECT 320.495 51.980 325.585 52.180 ;
        RECT 324.335 73.400 328.900 73.600 ;
        RECT 320.975 72.560 321.265 72.760 ;
        RECT 321.020 72.760 321.220 74.240 ;
        RECT 320.975 74.240 321.265 74.440 ;
        RECT 260.475 75.500 262.405 75.700 ;
        RECT 310.475 75.500 312.405 75.700 ;
        RECT 317.615 75.920 324.625 76.120 ;
        RECT 260.475 52.820 262.405 53.020 ;
        RECT 254.255 78.440 258.865 78.640 ;
        RECT 263.855 78.440 268.465 78.640 ;
        RECT 273.455 78.440 278.065 78.640 ;
        RECT 314.255 77.600 318.865 77.800 ;
        RECT 287.855 77.600 290.545 78.020 ;
        RECT 307.055 77.600 309.745 78.020 ;
        RECT 314.255 77.800 316.465 78.020 ;
        RECT 284.015 78.020 316.465 78.220 ;
        RECT 284.015 78.220 287.665 78.440 ;
        RECT 283.055 78.440 287.665 78.640 ;
        RECT 292.655 78.220 297.265 78.640 ;
        RECT 302.255 78.220 306.865 78.640 ;
        RECT 317.615 78.440 323.185 78.640 ;
        RECT 324.335 78.440 328.900 78.640 ;
        RECT 264.575 79.280 266.505 79.480 ;
        RECT 302.255 79.280 303.985 79.480 ;
        RECT 314.575 79.280 316.505 79.480 ;
        RECT 310.475 83.060 312.405 83.260 ;
        RECT 322.895 83.480 328.900 83.680 ;
        RECT 310.475 52.820 312.405 53.020 ;
        RECT 320.975 52.820 322.225 53.020 ;
        RECT 324.335 53.240 328.900 53.440 ;
        RECT 225.455 78.440 230.065 78.640 ;
        RECT 235.055 78.440 239.665 78.640 ;
        RECT 210.475 45.260 212.405 45.460 ;
        RECT 214.575 49.040 216.505 49.240 ;
        RECT 214.575 56.600 216.505 56.800 ;
        RECT 176.495 66.680 184.465 66.880 ;
        RECT 234.095 66.680 242.065 66.880 ;
        RECT 215.375 57.440 217.585 57.640 ;
        RECT 210.475 75.500 212.405 75.700 ;
        RECT 210.475 67.940 212.405 68.140 ;
        RECT 214.575 64.160 216.505 64.360 ;
        RECT 214.575 71.720 216.505 71.920 ;
        RECT 210.475 52.820 212.405 53.020 ;
        RECT 167.855 78.440 172.465 78.640 ;
        RECT 177.455 78.440 182.065 78.640 ;
        RECT 187.055 78.440 191.665 78.640 ;
        RECT 196.655 78.440 201.265 78.640 ;
        RECT 215.855 78.440 220.465 78.640 ;
        RECT 214.575 11.240 216.505 11.440 ;
        RECT 214.575 18.800 216.505 19.000 ;
        RECT 224.975 18.800 232.465 19.000 ;
        RECT 214.575 26.360 216.505 26.560 ;
        RECT 170.735 20.060 176.305 20.260 ;
        RECT 168.815 11.660 174.865 11.860 ;
        RECT 188.015 11.660 195.025 11.860 ;
        RECT 214.895 24.680 216.145 24.880 ;
        RECT 205.295 11.660 207.505 11.860 ;
        RECT 243.695 27.200 246.385 27.400 ;
        RECT 194.255 2.000 206.500 2.200 ;
        RECT 194.255 2.200 200.305 2.420 ;
        RECT 206.255 2.200 206.500 2.420 ;
        RECT 206.255 2.420 206.545 2.620 ;
        RECT 190.415 2.420 200.305 2.840 ;
        RECT 186.575 2.840 201.745 3.040 ;
        RECT 186.575 3.040 190.705 3.260 ;
        RECT 182.735 3.260 190.705 3.680 ;
        RECT 178.895 3.680 195.505 3.880 ;
        RECT 210.475 30.140 212.405 30.340 ;
        RECT 236.015 8.720 242.065 8.920 ;
        RECT 216.335 15.020 222.865 15.220 ;
        RECT 234.575 12.920 242.545 13.120 ;
        RECT 214.575 33.920 216.505 34.120 ;
        RECT 176.495 15.440 179.665 15.640 ;
        RECT 194.255 15.020 194.545 15.220 ;
        RECT 194.255 15.220 194.500 15.440 ;
        RECT 186.575 15.440 194.500 15.640 ;
        RECT 210.475 7.460 212.405 7.660 ;
        RECT 226.415 7.460 230.545 7.660 ;
        RECT 210.475 37.700 212.405 37.900 ;
        RECT 282.620 1.160 317.425 1.360 ;
        RECT 282.620 1.360 282.820 2.000 ;
        RECT 282.575 2.000 282.865 2.200 ;
        RECT 296.495 23.000 299.185 23.200 ;
        RECT 325.295 23.000 328.900 23.200 ;
        RECT 316.655 34.760 320.785 34.960 ;
        RECT 319.055 17.540 321.265 17.960 ;
        RECT 317.615 17.960 328.900 18.160 ;
        RECT 325.295 18.160 327.985 18.580 ;
        RECT 270.575 25.940 271.825 26.140 ;
        RECT 318.095 23.840 321.265 24.040 ;
        RECT 319.100 24.040 321.265 24.260 ;
        RECT 319.100 24.260 327.505 24.460 ;
        RECT 319.100 24.460 323.185 24.880 ;
        RECT 321.935 24.880 323.185 25.100 ;
        RECT 321.935 25.100 325.585 25.300 ;
        RECT 319.100 24.880 319.300 25.940 ;
        RECT 319.100 25.940 320.305 26.140 ;
        RECT 271.535 15.860 274.705 16.060 ;
        RECT 303.215 11.660 307.825 11.860 ;
        RECT 264.575 26.360 266.505 26.560 ;
        RECT 314.575 26.360 316.505 26.560 ;
        RECT 304.175 12.500 305.425 12.700 ;
        RECT 273.455 6.200 279.025 6.400 ;
        RECT 260.475 7.460 262.405 7.660 ;
        RECT 284.495 6.200 288.625 6.400 ;
        RECT 314.575 3.680 316.505 4.100 ;
        RECT 299.375 4.100 328.945 4.300 ;
        RECT 299.375 4.300 327.985 4.520 ;
        RECT 297.935 4.520 327.985 4.720 ;
        RECT 297.935 4.720 301.105 4.940 ;
        RECT 297.455 4.940 301.105 5.140 ;
        RECT 316.655 4.720 323.185 5.140 ;
        RECT 297.455 5.140 297.700 5.360 ;
        RECT 291.695 5.360 297.700 5.780 ;
        RECT 289.775 5.780 299.665 5.980 ;
        RECT 294.095 5.980 298.225 6.400 ;
        RECT 323.375 5.360 327.505 5.560 ;
        RECT 323.375 5.560 324.145 5.780 ;
        RECT 317.135 5.780 324.145 5.980 ;
        RECT 319.535 5.980 324.145 6.200 ;
        RECT 319.535 6.200 325.105 6.400 ;
        RECT 253.775 12.920 261.745 13.120 ;
        RECT 314.575 41.480 316.505 41.680 ;
        RECT 284.495 5.360 289.105 5.560 ;
        RECT 264.575 18.800 266.505 19.000 ;
        RECT 260.475 30.140 262.405 30.340 ;
        RECT 310.475 30.140 312.405 30.340 ;
        RECT 321.020 30.980 321.700 31.400 ;
        RECT 319.055 31.400 323.665 31.600 ;
        RECT 264.575 11.240 266.505 11.440 ;
        RECT 302.255 5.360 307.825 5.560 ;
        RECT 307.055 5.560 307.825 5.780 ;
        RECT 307.055 5.780 310.705 5.980 ;
        RECT 317.615 33.080 328.900 33.280 ;
        RECT 253.295 10.400 255.505 10.600 ;
        RECT 314.575 11.240 316.505 11.440 ;
        RECT 326.735 7.880 328.900 8.080 ;
        RECT 310.475 15.020 312.405 15.220 ;
        RECT 295.535 18.800 309.220 19.000 ;
        RECT 309.020 19.000 309.220 19.220 ;
        RECT 314.575 18.800 316.505 19.220 ;
        RECT 309.020 19.220 324.145 19.420 ;
        RECT 317.615 19.420 324.145 19.640 ;
        RECT 317.615 19.640 325.585 19.840 ;
        RECT 264.575 33.920 266.505 34.120 ;
        RECT 314.575 33.920 316.505 34.120 ;
        RECT 319.055 15.020 321.265 15.220 ;
        RECT 310.475 7.460 312.405 7.660 ;
        RECT 323.855 20.480 326.545 20.680 ;
        RECT 321.455 33.920 321.745 34.120 ;
        RECT 321.500 34.120 321.700 35.600 ;
        RECT 320.880 35.600 321.700 35.800 ;
        RECT 292.175 15.440 300.145 15.640 ;
        RECT 252.815 15.440 256.465 15.640 ;
        RECT 255.695 15.640 256.465 15.860 ;
        RECT 255.695 15.860 257.425 16.060 ;
        RECT 322.895 15.440 325.105 15.860 ;
        RECT 320.015 15.860 328.465 16.060 ;
        RECT 300.815 19.640 305.425 20.060 ;
        RECT 284.015 20.060 316.465 20.260 ;
        RECT 314.255 20.260 316.465 20.480 ;
        RECT 285.935 20.260 290.545 20.680 ;
        RECT 305.615 20.260 309.745 20.680 ;
        RECT 314.255 20.480 318.865 20.680 ;
        RECT 315.695 20.680 318.865 20.900 ;
        RECT 315.695 20.900 320.785 21.100 ;
        RECT 319.535 21.100 320.785 21.320 ;
        RECT 319.535 21.320 327.025 21.520 ;
        RECT 322.895 2.840 328.900 3.040 ;
        RECT 318.575 22.160 321.265 22.360 ;
        RECT 260.475 37.700 262.405 37.900 ;
        RECT 310.475 37.700 312.405 37.900 ;
        RECT 317.615 36.440 325.060 36.640 ;
        RECT 324.860 36.640 325.060 38.120 ;
        RECT 324.860 38.120 328.900 38.320 ;
        RECT 254.255 40.640 257.905 40.840 ;
        RECT 273.455 40.640 277.105 40.840 ;
        RECT 314.255 39.800 318.865 40.000 ;
        RECT 285.935 39.800 290.545 40.220 ;
        RECT 295.535 39.800 300.145 40.220 ;
        RECT 305.135 39.800 309.745 40.220 ;
        RECT 314.255 40.000 316.465 40.220 ;
        RECT 284.015 40.220 316.465 40.420 ;
        RECT 284.015 40.420 286.705 40.640 ;
        RECT 283.055 40.640 286.705 40.840 ;
        RECT 292.655 40.420 295.345 40.840 ;
        RECT 302.255 40.420 305.905 40.840 ;
        RECT 307.535 40.420 309.745 40.840 ;
        RECT 317.615 40.640 326.065 40.840 ;
        RECT 79.535 8.300 87.025 8.500 ;
        RECT 58.415 2.000 71.665 2.420 ;
        RECT 56.975 2.420 75.505 2.620 ;
        RECT 94.895 2.420 106.225 2.620 ;
        RECT 68.015 2.620 75.505 2.840 ;
        RECT 94.895 2.620 98.545 2.840 ;
        RECT 68.015 2.840 79.345 3.040 ;
        RECT 85.295 2.840 98.545 3.040 ;
        RECT 75.695 3.040 79.345 3.260 ;
        RECT 85.295 3.040 90.865 3.260 ;
        RECT 75.695 3.260 90.865 3.460 ;
        RECT 80.975 26.780 85.585 26.980 ;
        RECT 78.575 78.440 83.185 78.640 ;
        RECT 39.215 2.000 56.305 2.200 ;
        RECT 20.015 2.000 37.540 2.420 ;
        RECT 39.215 2.200 40.945 2.420 ;
        RECT 8.495 2.420 40.945 2.620 ;
        RECT 27.695 2.620 40.945 2.840 ;
        RECT 27.695 2.840 52.465 3.040 ;
        RECT 27.695 3.040 33.265 3.260 ;
        RECT 37.295 3.040 52.465 3.260 ;
        RECT 7.055 3.260 33.265 3.460 ;
        RECT 37.295 3.260 60.145 3.460 ;
        RECT 26.255 3.460 33.265 3.680 ;
        RECT 37.295 3.460 48.625 3.680 ;
        RECT 14.575 3.460 16.505 3.880 ;
        RECT 67.535 3.680 67.825 3.880 ;
        RECT 26.255 3.680 48.625 3.880 ;
        RECT 26.255 3.880 44.785 4.100 ;
        RECT 46.895 3.880 48.625 4.100 ;
        RECT 64.575 3.680 66.505 4.100 ;
        RECT 67.535 3.880 67.780 4.100 ;
        RECT 18.095 4.100 44.785 4.300 ;
        RECT 46.895 4.100 67.780 4.300 ;
        RECT 83.855 4.100 94.705 4.300 ;
        RECT 18.095 4.300 20.305 4.520 ;
        RECT 40.175 4.300 44.785 4.520 ;
        RECT 46.895 4.300 63.985 4.520 ;
        RECT 64.655 4.300 67.780 4.520 ;
        RECT 83.855 4.300 87.025 4.520 ;
        RECT 93.455 4.300 94.705 4.520 ;
        RECT 40.175 4.520 63.985 4.720 ;
        RECT 64.655 4.520 68.305 4.720 ;
        RECT 74.255 4.520 87.025 4.720 ;
        RECT 93.455 4.520 102.385 4.720 ;
        RECT 7.535 4.520 12.145 4.940 ;
        RECT 16.655 4.520 20.305 4.940 ;
        RECT 35.855 4.300 39.505 4.940 ;
        RECT 40.175 4.720 43.825 4.940 ;
        RECT 66.095 4.720 68.305 4.940 ;
        RECT 74.255 4.720 83.185 4.940 ;
        RECT 93.455 4.720 94.225 4.940 ;
        RECT 66.095 4.940 83.185 5.140 ;
        RECT 89.135 4.940 94.225 5.140 ;
        RECT 5.135 4.940 43.825 5.140 ;
        RECT 55.055 4.720 62.545 5.140 ;
        RECT 5.135 5.140 6.865 5.360 ;
        RECT 43.580 5.140 43.825 5.360 ;
        RECT 45.455 4.720 45.745 5.360 ;
        RECT 55.055 5.140 56.305 5.360 ;
        RECT 58.940 5.140 62.545 5.360 ;
        RECT 78.575 5.140 83.185 5.360 ;
        RECT 91.535 5.140 94.225 5.360 ;
        RECT 2.255 5.360 6.865 5.560 ;
        RECT 11.855 5.140 16.465 5.560 ;
        RECT 21.455 5.140 26.065 5.560 ;
        RECT 32.015 5.140 37.105 5.560 ;
        RECT 43.580 5.360 50.020 5.560 ;
        RECT 58.940 5.360 64.465 5.560 ;
        RECT 70.415 5.140 75.025 5.560 ;
        RECT 91.535 5.360 111.025 5.560 ;
        RECT 32.015 5.560 36.145 5.780 ;
        RECT 49.820 5.560 50.020 5.780 ;
        RECT 51.215 5.360 56.305 5.780 ;
        RECT 58.940 5.560 59.140 5.780 ;
        RECT 72.335 5.560 75.025 5.780 ;
        RECT 78.575 5.360 83.665 5.780 ;
        RECT 91.535 5.560 91.780 5.780 ;
        RECT 31.535 5.780 36.145 5.980 ;
        RECT 49.820 5.780 59.140 5.980 ;
        RECT 72.335 5.780 91.780 5.980 ;
        RECT 72.335 5.980 74.065 6.200 ;
        RECT 89.615 5.980 91.780 6.200 ;
        RECT 32.015 5.980 35.665 6.400 ;
        RECT 70.415 6.200 74.065 6.400 ;
        RECT 89.615 6.200 93.265 6.400 ;
        RECT 51.215 5.980 54.865 6.620 ;
        RECT 50.735 6.620 55.345 6.820 ;
        RECT 116.495 72.560 117.745 72.760 ;
        RECT 107.375 55.760 108.625 55.960 ;
        RECT 110.475 75.500 112.405 75.700 ;
        RECT 160.475 75.500 162.405 75.700 ;
        RECT 88.175 78.020 89.905 78.220 ;
        RECT 107.375 78.020 109.105 78.220 ;
        RECT 139.535 43.580 143.665 43.780 ;
        RECT 97.775 78.440 102.385 78.640 ;
        RECT 126.575 78.440 131.185 78.640 ;
        RECT 136.175 78.440 140.785 78.640 ;
        RECT 145.775 78.440 150.385 78.640 ;
        RECT 158.255 78.440 162.865 78.640 ;
        RECT 110.475 52.820 112.405 53.020 ;
        RECT 110.475 67.940 112.405 68.140 ;
        RECT 160.475 67.940 162.405 68.140 ;
        RECT 160.475 52.820 162.405 53.020 ;
        RECT 114.575 49.040 116.505 49.240 ;
        RECT 110.475 45.260 112.405 45.460 ;
        RECT 110.475 83.060 112.405 83.260 ;
        RECT 114.575 71.720 116.505 71.920 ;
        RECT 88.175 55.760 89.425 55.960 ;
        RECT 68.975 78.440 73.585 78.640 ;
        RECT 10.475 75.500 12.405 75.700 ;
        RECT 60.475 75.500 62.405 75.700 ;
        RECT 1.775 55.760 9.265 55.960 ;
        RECT 10.475 45.260 12.405 45.460 ;
        RECT 64.575 56.600 66.505 56.800 ;
        RECT 14.575 49.040 16.505 49.240 ;
        RECT 10.475 52.820 12.405 53.020 ;
        RECT 10.475 67.940 12.405 68.140 ;
        RECT 60.475 67.940 62.405 68.140 ;
        RECT 60.475 52.820 62.405 53.020 ;
        RECT 14.575 56.600 16.505 56.800 ;
        RECT 1.775 74.660 9.265 74.860 ;
        RECT 64.575 49.040 66.505 49.240 ;
        RECT 67.055 49.040 68.785 49.240 ;
        RECT 5.135 78.440 9.265 78.640 ;
        RECT 60.475 45.260 62.405 45.460 ;
        RECT 30.575 59.540 34.225 59.740 ;
        RECT 20.975 78.440 25.585 78.640 ;
        RECT 1.775 47.360 5.425 47.560 ;
        RECT 1.775 70.880 9.265 71.080 ;
        RECT 14.575 79.280 16.505 79.480 ;
        RECT 14.575 64.160 16.505 64.360 ;
        RECT 14.575 71.720 16.505 71.920 ;
        RECT 64.575 71.720 66.505 71.920 ;
        RECT 30.575 78.440 35.185 78.640 ;
        RECT 40.175 78.440 44.785 78.640 ;
        RECT 52.175 64.160 57.745 64.360 ;
        RECT 64.575 64.160 66.505 64.360 ;
        RECT 49.775 78.440 54.385 78.640 ;
        RECT 14.575 11.240 16.505 11.440 ;
        RECT 42.095 11.240 45.745 11.440 ;
        RECT 64.575 11.240 66.505 11.440 ;
        RECT 21.935 8.300 27.985 8.500 ;
        RECT 3.215 12.500 3.505 12.700 ;
        RECT 3.260 12.700 3.505 12.920 ;
        RECT 3.260 12.920 4.465 13.120 ;
        RECT 30.095 12.920 38.065 13.120 ;
        RECT 39.695 12.920 47.665 13.120 ;
        RECT 10.475 15.020 12.405 15.220 ;
        RECT 60.475 15.020 62.405 15.220 ;
        RECT 1.775 17.960 9.265 18.160 ;
        RECT 14.575 18.800 16.505 19.000 ;
        RECT 64.575 18.800 66.505 19.000 ;
        RECT 66.575 17.960 67.300 18.160 ;
        RECT 67.100 18.160 67.300 19.640 ;
        RECT 66.575 19.640 67.300 19.840 ;
        RECT 0.815 22.160 3.985 22.360 ;
        RECT 35.855 23.000 37.585 23.200 ;
        RECT 14.575 26.360 16.505 26.560 ;
        RECT 64.575 26.360 66.505 26.560 ;
        RECT 60.475 7.460 62.405 7.660 ;
        RECT 10.475 30.140 12.405 30.340 ;
        RECT 60.475 30.140 62.405 30.340 ;
        RECT 1.775 33.080 9.265 33.280 ;
        RECT 14.575 33.920 16.505 34.120 ;
        RECT 64.575 33.920 66.505 34.120 ;
        RECT 12.815 40.220 22.705 40.420 ;
        RECT 20.975 40.420 22.705 40.640 ;
        RECT 17.615 40.420 18.865 40.840 ;
        RECT 20.975 40.640 24.625 40.840 ;
        RECT 7.055 25.520 11.665 25.720 ;
        RECT 67.055 33.080 67.345 33.280 ;
        RECT 67.100 33.280 67.300 34.760 ;
        RECT 67.100 34.760 67.825 34.960 ;
        RECT 55.055 36.440 57.745 36.640 ;
        RECT 10.475 37.700 12.405 37.900 ;
        RECT 60.475 37.700 62.405 37.900 ;
        RECT 41.615 10.400 48.625 10.600 ;
        RECT 60.335 6.620 67.825 6.820 ;
        RECT 1.775 6.620 8.740 6.820 ;
        RECT 8.495 6.820 8.740 7.040 ;
        RECT 8.495 7.040 8.785 7.240 ;
        RECT 12.335 6.620 18.340 6.820 ;
        RECT 18.095 6.820 18.340 7.040 ;
        RECT 18.095 7.040 18.385 7.240 ;
        RECT 10.475 7.460 12.405 7.660 ;
        RECT 107.375 17.960 109.105 18.160 ;
        RECT 148.175 3.680 155.665 3.880 ;
        RECT 127.535 8.300 135.505 8.500 ;
        RECT 114.575 11.240 116.505 11.440 ;
        RECT 159.695 2.000 161.905 2.200 ;
        RECT 98.735 18.800 104.785 19.000 ;
        RECT 98.735 19.000 99.505 19.220 ;
        RECT 96.815 19.220 99.505 19.420 ;
        RECT 150.575 18.800 151.300 19.000 ;
        RECT 151.100 19.000 151.300 19.220 ;
        RECT 151.100 19.220 163.345 19.420 ;
        RECT 146.735 8.300 151.345 8.500 ;
        RECT 123.695 3.260 129.265 3.460 ;
        RECT 100.175 11.660 105.745 11.860 ;
        RECT 110.255 23.420 113.905 23.620 ;
        RECT 108.335 8.720 110.065 8.920 ;
        RECT 143.375 8.720 144.625 8.920 ;
        RECT 99.215 7.880 100.465 8.080 ;
        RECT 140.495 4.520 144.625 4.720 ;
        RECT 112.655 5.360 116.305 5.560 ;
        RECT 137.615 10.820 144.145 11.020 ;
        RECT 110.475 7.460 112.405 7.660 ;
        RECT 110.475 30.140 112.405 30.340 ;
        RECT 160.475 30.140 162.405 30.340 ;
        RECT 120.335 4.520 139.825 4.720 ;
        RECT 120.335 4.720 123.505 4.940 ;
        RECT 117.935 4.940 123.505 5.140 ;
        RECT 132.815 4.720 135.025 5.140 ;
        RECT 129.980 4.720 130.180 5.360 ;
        RECT 118.415 5.140 123.025 5.560 ;
        RECT 129.935 5.360 130.225 5.560 ;
        RECT 110.475 15.020 112.405 15.220 ;
        RECT 118.415 6.200 122.065 6.400 ;
        RECT 160.475 15.020 162.405 15.220 ;
        RECT 114.095 2.840 121.585 3.040 ;
        RECT 114.575 33.920 116.505 34.120 ;
        RECT 110.475 37.700 112.405 37.900 ;
        RECT 160.475 37.700 162.405 37.900 ;
        RECT 107.375 41.480 109.105 41.680 ;
        RECT 97.775 6.200 102.865 6.400 ;
        RECT 138.575 34.340 144.625 34.540 ;
        RECT 108.815 6.200 112.465 6.400 ;
        RECT 110.255 6.400 112.465 6.620 ;
        RECT 110.255 6.620 113.905 6.820 ;
        RECT 131.375 6.200 131.665 6.400 ;
        RECT 131.375 6.400 131.620 6.620 ;
        RECT 128.015 6.620 131.620 6.820 ;
        RECT 133.295 2.840 136.945 3.040 ;
        RECT 104.495 3.260 113.905 3.460 ;
        RECT 104.495 3.460 110.065 3.680 ;
        RECT 103.055 3.680 110.065 3.880 ;
        RECT 114.575 3.680 116.505 3.880 ;
        RECT 160.475 7.460 162.405 7.660 ;
  END
END CFGMEM_IHP_LEFT16
END LIBRARY

